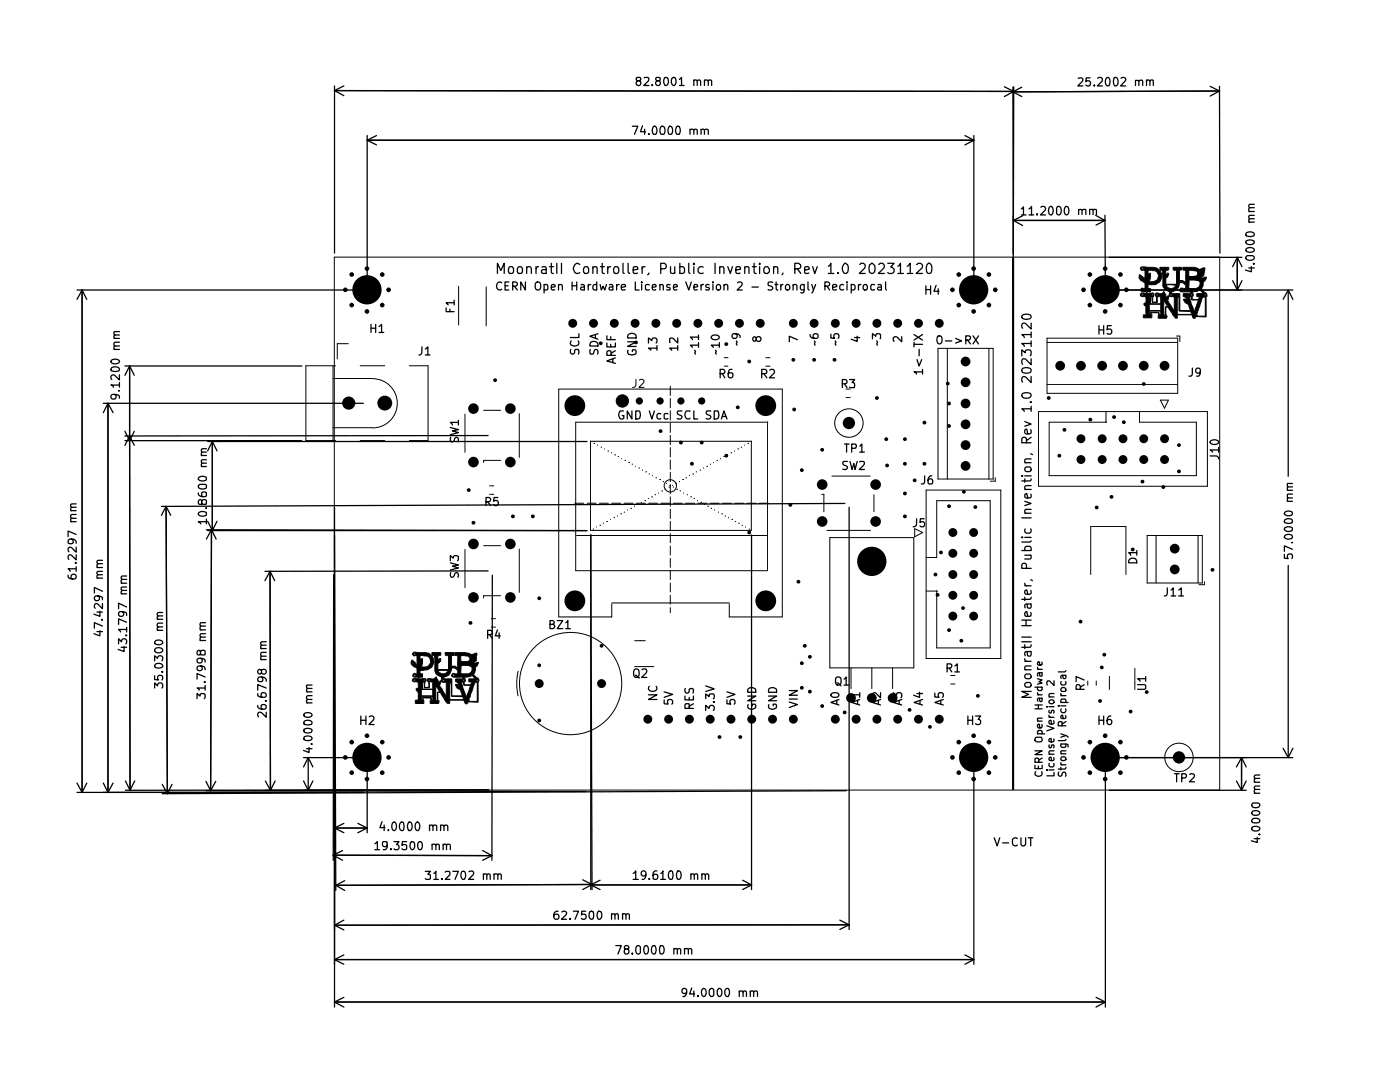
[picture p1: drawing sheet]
<svg xmlns="http://www.w3.org/2000/svg" width="279mm" height="216mm" viewBox="0 0 279 216" stroke-linecap="round" stroke-linejoin="round" font-family="sans-serif">
<g fill="none" stroke="#000" stroke-width=".2">
<path d="M66.7 51.3h176.7v106.3h-176.7zM91.5 57.1v7.8M97 57.2v7.8M227.5 55.1h.1M227.5 55.1l.6 .9 .2 .1M227.5 55.1l.2 .3M227.6 53.6h.1M227.6 53.6v-.2l.2-.1h2.4a1.75 1.75 0 0 1 1.7 1.7 1.75 1.75 0 0 1-1.5 1.8h-1.3v.8h.5v.7h-.7v.3l1.3-.1a.52 .52 0 0 1-.2 .8v1h.8v-1.1M227.6 53.6l.2 .3h2.1a1.15 1.15 0 0 1 1.3 1 1.15 1.15 0 0 1-1.1 1.3h-.7l.2-.8-.1-.9M227.6 58.8h.2M227.6 53.6h.2M227.7 57.8h.1"/>
<path d="M227.7 55.4h.1M227.7 57.8a.34 .34 0 0 0 .4 .5l.7-.1v.4l-.9-.2-.2 .2a.36 .36 0 0 0 .1 .6h.9v1.3M227.7 55.4l.7 .9v-.8M227.8 57.6h.1M227.8 57.6l-.1 .2M227.8 53.4h.3l.1 .3-.4 .1zM227.8 58.7l.2-.1 .2 .3-.4 .1zM228 57.7h.1M228 53.3h.1M228 57.7l.3 .1-.1 .2h-.3l-.1-.2M228 57.7l-.2 .1M228.2 58.8h1.6"/>
<path d="M228.3 56.1h.1M228.3 56.1a1.38 1.38 0 0 0-.9-1.3 1.26 1.26 0 0 0 1 1.6l.1 1.2h-.7M228.4 55.5h.1M228.4 53.9h.1M228.4 55.5h.7M228.5 53.9l-.1 1.6M228.6 59.2h.1M229.1 55.5h.1M229.1 53.9v.8l.4-.2M229.4 55.1h.1M229.4 55.1l-.3 .4M229.4 55.1l-.2 .4"/>
<path d="M229.5 54.5h.1M229.6 59.2h.1M229.6 59.9h.1M229.6 59.2v1.4M229.6 59.2h.2M229.8 59.2h.1M229.8 59.2l.2 1.2h1v-1.1h.6v1.3h-2.2M229.8 58.7h.3v.2l-.2 .1zM230.1 59.2h.1M230.5 58.8h.2M230.7 58.7l.4 .1-.4 .2zM230.8 59.2h.1"/>
<path d="M231.5 53.8h.1M231.5 53.8v-.5h1.8v.5l-.6 .2v.8M231.5 53.8l.5 .1 .2 3.4a1.65 1.65 0 0 0 1.1 .9l.1 1 1 .1M231.9 58.6h.1M231.9 53.9h.1M232.1 56.9h.1M232.1 56.9h2.6M232.1 55.3h.6M232.2 58.3h.1M232.2 58.3l-.3 .3M232.2 58.3v-.1l.5 .6v.6M232.2 58.5h.1"/>
<path d="M232.2 59.9h.1M232.2 58.6h-.9l-.4-.2-.4 .2v.3l.3 .3M232.2 59.9l.8 1.2M232.2 58.5v.2M232.2 59.9v3M232.7 54.8h.1M232.7 59.4h.1M232.7 56.9h.1M232.7 55.3h.1M232.7 56.9a1.03 1.03 0 0 0 1 .7 1.03 1.03 0 0 0 1-.7M232.7 59.4l.1 .1M232.8 59.5h.1"/>
<path d="M232.8 55.2h.1M232.8 55.1h.1M232.8 55.1v.1M232.8 55.2l-.1 .1M232.9 59.6l-1.3 .1M232.9 55l-.8 .1M233.1 59.7h.1M233.1 54.7h.1M233.1 59.2h.1M233.1 54.7l-.2 .3M233.1 59.2l-.2 .4M233.3 59h.1"/>
<path d="M233.3 59l-.5 .3v.2M233.3 59l-.3 .9 1.4 2.2v-2.8M233.3 58.8h.2M233.4 58.3h.4M233.7 58.7l.2 .1v.2h-.3l-.1-.2zM233.8 58.3h.1M234.2 53.8h.1M234.4 59.3h.1M234.7 56.9h.1M234.8 58.6h.1M234.8 56.2h.6M235 59.3h.1"/>
<path d="M235 59.3l-.1 3.4M235 59.3l.3-.1v2.9h2.3l.2 .6h-3.8M235.4 57.8h.1M235.4 56.2h.1M235.4 57.8l.3 .5h1.9M235.4 56.1h.7l.5 .5h-.1a1.13 1.13 0 0 0-1.1-.4zM235.7 56.3h.1M235.7 56.1h.1M235.7 57.7h.3v.3h-.4l-.1-.2zM236.1 58.8h1.5M236.2 59.7h.1M236.2 59.8h.3"/>
<path d="M236.2 59.7l.6 .1M236.3 56.3h.1M236.4 59.2h.1M236.4 59.2l.9 .1M236.5 59.8h.1M236.5 59.8l.5 .7M236.5 59.8l.2 .4M236.6 53.9h.1M236.6 59.3l.2 .5M236.6 57.6h.1M236.6 55.2h.1M236.6 57.6a1.06 1.06 0 0 0-1.2-1.2 1.71 1.71 0 0 1-1.6 1.9v.1l.3 .2h1.4v3.4h2.1l-.1-.3a1.63 1.63 0 0 0-.9-1.3l-.4-.7"/>
<path d="M236.6 53.9v2.5l-.6-.4h-.6v-2.1l.4-.1v-.5h-1.7v.5l.2 .1h.5v2.8h-2.1v-1.2a.68 .68 0 0 0 .4-1.1l-.4 .4M236.6 55.2h2.9M236.6 55.8h3.8M236.6 55.4h2.9M236.8 59.8h.1M237.2 53.9l.1 1.3M237.3 59.3h.1M237.3 59.3h.4l.1 .6h1.4l-.9 2.2M237.3 59.3l1 2.8M237.3 55.8l-.1 1.8M237.6 58.3h.1M237.6 58.3l.1 .1-.3 .2h-1.3v.6h.3"/>
<path d="M237.6 58.8l.1 .2 .3-.2M237.6 58.8l.1-.1h.3v.1M237.7 59.4h.2M237.9 59.7h.1M238 58.3h.1M238 58.8h.1M238 55.2l.7-.1a.59 .59 0 0 0 .3-.7 .59 .59 0 0 0-.7-.4l-2-.1-.2-.1v-.5h2.3l1 .5 .3-.2 .8-.2-.1 1a1.43 1.43 0 0 1-.8 1.1l.9 .1M238 58.3l.8-.1 .7-.3 .7 .7h-1.4v.6l.6 .1-.2 .5h-1l-.3-.1v-.5l.3-.3zM238.2 55.8l1.8 .2M238.8 58.8h1.5M239 54.5h.1M239 56a.57 .57 0 0 1 .5 .6 1 1 0 0 1-.8 1l-3.1-.1-.2 .3"/>
<path d="M239 54.5h.7M239.4 55.4h.1M239.5 55.4h.1M239.5 55.2h.1M239.7 54.5h.1M239.8 54.4h.1M239.8 55.6h.1M239.8 55.6l.7-.3h.3l-.3 .6a1.13 1.13 0 0 0-.4 1.1l-.3 .7 .7 .7M239.8 54.4l.3-.6-.1-.1-.3 .8M239.8 54.4l-.1 .1M239.9 55.5h.1M240 56h.1"/>
<path d="M240 59.3h.1M240 59.3h.5v3.8l-1.7-.1M240 59.3l-1.2 3.7M240.1 55.9h.1M240.1 55.8h.1M240.1 55.9l-.1 .1M240.1 55.8v.1M240.2 55.8h.1M240.3 58.8h.1M240.3 58.8l.3-.1 .1 .1-.2 .2zM240.4 55.8h.1M240.4 55.7h.1"/>
<path d="M240.4 56h.1M240.4 55.7v.1M240.5 55.6h.1M240.5 55.6l-.1 .1M240.5 58.4h.1M240.5 58.4l.4 .4-.2 .4v4h-2l-.2 .3a.44 .44 0 0 1-.4-.1 .44 .44 0 0 1-.2-.4M240.8 59.1h.1M66.5 73v14.9M66.5 75.5h7.8M67 73h-6v14.9h6M69.5 68.6h-2.2v3M71.9 73h4.9"/>
<path d="M74.4 75.6a4.9 4.9 0 0 1 4.9 4.9 4.9 4.9 0 0 1-4.9 4.9M81.7 73h3.7v14.9h-3.7M126.9 75.7v1.1a.57 .57 0 0 1-.7 .5M127.6 75.9l.1-.1a.6 .6 0 0 1 .8 .1l-.1 .5-.9 .9h1M133.8 77v1.9M133.8 79.5v1.9M144.5 73.1h.8M144.5 71.4h.8M152.8 73.1h.9M152.8 71.4h.9M168.8 77.6h.9M168.8 79.3h.9"/>
<path d="M187.2 69.5h11v26.1h-11zM189.1 69.5v26.1M197.4 69.5v26.1M209 68.3h26M209 67.5h26v11h-26zM209 76.7h26M228.3 60.6h.1M228.3 60.6v.3l.4 .2M228.4 60.6h.1M228.4 60.6l.3 .4-.2-.2M228.7 62h.1M228.7 61.1h.1"/>
<path d="M228.7 60.5h.1M228.7 62h2.9v-1.3h-2.2v-1.5v2.8M228.7 62.5l.1 .3h-.6v.6h1.7l-.1-.6M228.7 62.5h.7M228.7 61.1v1.4M228.7 60.5h-.4v.1M229.4 60.5h.1M229.4 62.8h.1M229.4 62.8v-.7h2.2v.8M229.6 62.6h.1M229.6 62.6l-.2 .2M229.8 62.8h.1"/>
<path d="M231.2 62.7h.1M231.4 60.6h.1M231.6 79.8h1.6l-.8 1.6zM232.7 62.9h.1M232.8 63.2h.1M233 61.1h.1M233 61.1l-.4 .1-.1 1.7h-1.1l-.1-.6h-1.7v.3M234 62.7h.1M234 62.7l-.9-1.4h-.4v1.5l.1 .2v.5h-1.7l.1-1.1h-1.5l.1 .4M234 62.7l.6 .8h.3v-.7h2.9l.1 .2M234.8 67.1h.7v1.1M236.7 60.2h.1"/>
<path d="M236.7 60.2l.3 .3M237 60.5h.1M237.7 62.7h.1M237.9 63h.9M238.3 62.1h.1M238.8 63h.1M66.5 85.3h7.8M71.9 87.9h4.9M92.8 82.6v7.7M96.5 81.9h3.4M97.7 98.6h.9M97.7 96.9h.9"/>
<path d="M99.9 91.9h-3.4v.4M103.6 82.5v8.8M117.9 88.1h.1M117.9 88.1v17.7h32v-17.7M117.9 88.1h32M118.5 88.5h.1M119.2 88.8h.1M120 89.2h.1M120.6 89.6h.1M121.3 90h.1M122 90.3h.1M122.7 90.8h.1"/>
<path d="M123.4 91.1h.1M124 91.5h.1M124.7 91.9h.1M125.5 92.3h.1M126.2 92.6h.1M126.8 93h.1M127.5 93.4h.1M128.2 93.8h.1M128.7 99.9h.1M128.9 94.1h.1M129.4 99.5h.1M129.5 94.6h.1"/>
<path d="M130 99.1h.1M130.2 94.9h.1M130.7 98.7h.1M130.9 95.3h.1M131.4 98.4h.1M131.7 95.7h.1M132.1 98h.1M132.3 96.1h.1M132.8 97.6h.1M133 96.4h.1M133.5 97.2h.1M133.7 96.9h.1"/>
<path d="M133.8 82v1.8M133.8 84.4v1.9M133.8 86.9v1.8M133.8 89.3v1.9M133.8 91.8v1.8M133.8 94.2v1.9M133.8 96.7v1.9M133.8 99.1v1.9M134.2 96.9h.1M134.4 97.2h.1M134.9 96.4h.1M135 97.6h.1"/>
<path d="M135.6 96.1h.1M135.7 98h.1M136.2 95.7h.1M136.4 98.4h.1M136.9 95.3h.1M137.2 98.7h.1M137.6 94.9h.1M137.8 99.1h.1M138.3 94.6h.1M138.5 99.5h.1M138.9 94.1h.1M139.2 99.9h.1"/>
<path d="M139.7 93.8h.1M140.4 93.4h.1M141.1 93h.1M141.7 92.6h.1M142.4 92.3h.1M143.1 91.9h.1M143.8 91.5h.1M144.4 91.1h.1M145.1 90.8h.1M145.9 90.3h.1M146.6 90h.1M147.2 89.6h.1"/>
<path d="M147.9 89.2h.1M148.6 88.8h.1M149.3 88.5h.1M149.9 88.1h.1M153.2 84.2v29.6M153.2 84.2h-38.3v29.7h38.3M164 98.6h.4v3.5M166 95h7.7M174.4 98.7v3.4M184.8 97.8h14.9v33.6h-14.9zM198.6 95.3v.7h-1M207.3 82.1h33.7v14.9h-33.7z"/>
<path d="M220.7 84.2h.1M220.7 82.1v2.1M227.4 82.1v2.1h11.4v10.7h-29.4v-10.7h11.3M92.8 109.6v7.7M96.5 108.9h3.4M99.9 118.9h-3.4v.4M103.6 109.6v8.6M114.7 100.4h1.8M115.1 106.8h38.1M117.2 100.4h1.8M118.4 105.6h.1M119 105.2h.1"/>
<path d="M119.6 100.4h1.8M119.7 104.8h.1M120.4 104.4h.1M121.1 104.1h.1M121.8 103.6h.1M122.1 100.4h1.8M122.5 103.3h.1M123.2 103h.1M123.9 102.5h.1M124.5 102.2h.1M124.5 100.4h1.8M125.2 101.8h.1"/>
<path d="M125.9 101.4h.1M126.6 101h.1M127 100.4h1.8M127.3 100.7h.1M128 100.2h.1M129.5 100.4h1.7M131.9 100.4h1.8M133.8 101.6v1.9M133.8 104.1v1.8M133.8 106.5v1.8M133.8 109v1.7M133.8 111.4v1.8"/>
<path d="M133.8 113.9v1.8M133.8 116.3v1.8M133.8 118.8v1.8M134.4 100.4h1.7M136.8 100.4h1.8M139.3 100.4h1.8M139.9 100.2h.1M140.5 100.7h.1M141.2 101h.1M141.7 100.4h1.8M141.9 101.4h.1M142.6 101.8h.1"/>
<path d="M143.3 102.2h.1M144 102.5h.1M144.2 100.4h1.8M144.7 103h.1M145.4 103.3h.1M146 103.6h.1M146.6 100.4h1.8M146.7 104.1h.1M147.4 104.4h.1M148.1 104.8h.1M148.8 105.2h.1M149.1 100.4h1.8"/>
<path d="M149.5 105.6h.1M151.6 100.4h1.7M165 105.8h8.7M165.6 107.3h16.8v26h-16.8zM182.5 105.5l1.6 .8-1.6 .8zM184.8 111.3h2.1v-11.4h10.7v29.4h-10.7v-11.4M184.8 117.9h2.1M186.9 117.9h.1M217.7 114.6v-9.5h7v9.5M228.9 106.8h11v9.5h-11zM230.7 106.8v9.5M239.1 106.8v9.5"/>
<path d="M240.4 116.1v.6h-1.1M82.3 135.7h.1M82.3 130.5l.3 .4 1.9-.1a1.27 1.27 0 0 1 1.4 .8 1.17 1.17 0 0 1-.9 1.5h-.8l.1-1.7-.5 .2v-.8M82.3 130.5l.2-.4 2.4 .1a1.74 1.74 0 0 1 1.7 1.9 1.74 1.74 0 0 1-1.9 1.6l-.9 .1v.7h.5v.6h-.7v.4l1.3-.1 .2 .3-.3 .4v1.1h.8v-.8l-.3-.6 .1-.4 1.6 .1M82.3 135.7v.2l.3 .2h.8M82.3 135.7h.2M82.3 130.5h.2M82.4 134.8h.1M82.5 130.5l.3-.2 .1 .3h-.4zM82.5 135.6h.4l-.1 .3-.3-.1zM82.6 132.7l-.4-.7 .2 .4 .7 .6M82.6 134.6l.2-.1 .2 .3-.4 .2z"/>
<path d="M82.7 130.1h.1M82.9 135.7h1.6M83.1 133.1a1.25 1.25 0 0 0-.9-1.4 .91 .91 0 0 0 .6 1.4l.4 .2v1.2h-.1a.41 .41 0 0 0-.7 0 .41 .41 0 0 0 .2 .6h.9v.4l-1-.1-.2 .3M83.1 137.5h.1M83.1 130.8h.1M83.1 137.5l.3 .3M83.1 137.5l.2 .2M83.1 130.8l.1 1.6M83.2 132.4h.1M83.2 132.4l-.1 .8-.4-.4M83.2 132.4h.7M83.3 137.7h.1"/>
<path d="M83.3 137.7l.1 .1M83.4 138h.1M83.4 137.8h.1M83.4 137.4h.1M83.4 136.1h.1M83.4 138l.1 1.7h-.6v.7h1.7v-.7h-.2v-.4h1.5v1.1h1.6v-.6M83.4 136.1v1.3M83.4 137.4l-.3-.1v.5l.3 .2M83.5 139.4h.6M83.9 132.4h.1M84.2 139.7h.1M84.2 132h.1"/>
<path d="M84.2 139.7l.1-.1v-.4h1.8l.1 .6M84.2 136.1v1.5h2.2l-.3-.1M84.2 136.1l-.1 2.8M84.2 139.7l-.1-.8h2.3l-.1 .9M84.2 137.5h1.9M84.2 132l-.3 .4M84.3 139.4h.1M84.3 137.5v-1.4h.3l.1 1.1h1v-1.1h.7v2.8h-2.9M84.5 139.7h.1M84.5 135.6h.3v.2l-.2 .1zM84.8 136.1h.1M85.3 135.7h.1"/>
<path d="M85.4 135.7l.1 .2M85.4 135.7l.2-.1 .3 .1-.4 .2M85.5 135.9h.1M86.1 137.5h.1M86.2 139.8h.1M86.4 136.6h1.2M86.7 135.5h.1M86.7 130.9h.1M86.8 135.4h.1M86.8 133.8h.1M86.8 133.8h2.6M86.8 135.4l-.1 .1"/>
<path d="M86.8 132.2h.7M86.8 132h.8M87 135.6h.1M87 135.4h.1M87 135.1h.1M87 135.1l.5 .7v.5M87 135.4v.2M87 135.1l-.2 .3M87 136.9h.1M87 136.9v2.9M87 136.9l.7 1.1M87.4 131.7h.1"/>
<path d="M87.4 131.7v-.8l.6-.2v-.5h-1.8v.5l.5 .1 .2 3.2a1.27 1.27 0 0 0 1.2 1M87.5 136.3h.1M87.5 133.8h.1M87.5 139.8h.1M87.5 133.8a1.03 1.03 0 0 0 .9 .7 1.03 1.03 0 0 0 1-.7M87.5 136.3v.1M87.5 136.4h.1M87.5 132.2h.1M87.5 132.1h.1M87.5 132.1v.1M87.6 136.6h.1M87.7 138h.1"/>
<path d="M87.7 138l-.4 .1v1.7h-1.1M87.8 131.6h.1M87.8 131.4h.1M87.8 136.1l-.2 .5zM87.8 131.6l-.2 .4M87.9 135.9h.1M87.9 135.9l-.4 .5M88 135.9h.1M88 135.9l-.3 .9 1.4 2.1v-2.8M88.1 135.8h.1M88.1 135h.1M88.1 135v.2"/>
<path d="M88.1 135.2h.1M88.1 135.2v.7l.1 .2M88.1 135.2h.4M88.2 136.1h.1M88.2 136.1h.9M88.3 135.6h.3v.3l-.2 .1-.2-.2zM88.5 135.2h.1M88.7 139.6h.1M88.7 139.6l-.8-1.4h-.5l.1 1.6M88.7 139.6h3.8M89.1 136.1h.1M89.4 133.8h.1"/>
<path d="M89.5 135.5h.1M89.5 133.1h.7a1.19 1.19 0 0 1 1.2 .5v-.1M89.7 136.2h.1M89.8 136.1h.1M89.8 136.1l-.1 3.5M89.8 136.1h.2M90 136.1h.1M90 136.1l.1 2.8 2.3 .1 .1 .6M90.1 134.8h.1M90.1 133.1h.1M90.1 134.8l.3 .3h2l-.1 .4M90.1 134.8h.2"/>
<path d="M90.1 133.1l.1-.1a1.16 1.16 0 0 1 1.2 .5M90.3 134.5h.1M90.3 134.5l-.2 .3M90.4 133.2h.1M90.4 133h.1M90.4 134.5h.2l.2 .3-.2 .2-.3-.1zM90.9 136.7h.1M90.9 136.6h.1M90.9 135.7h1.4M90.9 136.7h.4M90.9 136.6v.1M91.2 136.7h.1"/>
<path d="M91.2 136.7l.5 .6M91.3 136.7h.1M91.3 136.1h.1M91.3 130.8h.1M91.3 136.1h1.2M91.3 136.7l.5 .7M91.3 130.8l.1 .1M91.4 134.5h.1M91.4 133.5h.1M91.4 132.1h.1M91.4 130.9h.1M91.4 130.9v2.4l-.6-.4h-.7v-2.1h.5v-.6h-1.8l.1 .6 .6 .1v2.7h-2.1v-1.2l.2-.2a.58 .58 0 0 0 .3-.8l-.5 .3"/>
<path d="M91.4 134.5v-.6l-.7-.6h-.5l-.1 .4a1.57 1.57 0 0 1-1.6 1.4v.3l.3 .1h1.4v3.4h2.1l-.2-.6a1.19 1.19 0 0 0-.9-1.1l-.3-.5M91.4 132.7h3.7M91.4 132.1h2.9M91.4 132.2h2.8M91.7 137.3h.1M91.9 130.8l.1 1.3M92 136.1l1 3M92 132.7l-.1 1.8M92.3 135.5h.1M92.3 135.5h-1.4v.6a.67 .67 0 0 1 .6 .6l-.6-.1M92.3 135.7l.1 .2 .3-.2M92.3 135.7l.2-.1 .2 .1"/>
<path d="M92.4 139.6h.1M92.5 136.1h.1M92.5 136.3v.4h1.4l-.9 2.4M92.5 136.3h.1M92.5 136.1v.2M92.5 139.6h.1M92.6 136.6h.1M92.6 139.9h1M92.7 135.2h.1M92.7 135.7h.1M92.7 135.2l.2 .8-.3 .1v.5M92.7 135.2l1.5-.4 .7 .7h-1.3v.6h.5l-.2 .6-1.3-.1"/>
<path d="M92.9 132.7l.7 .1h1.2M93 139.1h.1M93.6 139.9h.1M93.6 135.7h1.4M93.7 132.8l.3 .1a.86 .86 0 0 1 .1 1.2l-.5 .4-3.3-.1v.1M93.8 131.4h.1M93.8 131.4a.74 .74 0 0 0-.8-.5l-2.2-.1v-.6l2.6 .1 .8 .4 .1-.1 .9-.3-.2 1.5M93.8 131.4a.72 .72 0 0 1-.8 .7M94.2 132.3h.1M94.2 132.2h.1M94.2 132.2v.1M94.2 132.1h.1"/>
<path d="M94.3 132.1h.1M94.4 131.4h.1M94.4 132.4h.1M94.4 132.4l.8 .1M94.5 131.3h.1M94.5 132.5h.1M94.5 131.3l-.1 .1M94.8 132.8h.1M94.8 130.6h.1M94.8 136.1h.1M94.8 136.1h.4v3.9h-1.6v-.4zM94.8 132.8h-.1"/>
<path d="M94.8 130.6l-.3 .5v.3h-.7M94.8 130.6l-.3 .7M94.9 132.7h.1M95 132.7h.1M95 131.8h.1M95 131.8l-.6 .6M95.1 132.7h.1M95.1 132.6h.1M95.1 132.9h.1M95.1 132.6v.1M95.2 135.6h.1M95.2 132.6h.1"/>
<path d="M95.2 135.6h.2v.3l-.4-.2M95.2 135.6l-.2 .1M95.2 132.6l-.1 .1M95.2 132.5h.1M95.2 135.3h.1M95.2 135.3l.4 .3-.2 .5v4l-1.9-.1-.2 .4-.3 .1-.5-.8h-2.8v.7h-.4l-.6-.8M95.2 132.5v.1M95.5 132.2h.1M95.5 132.2h-.5l-.3 .3M95.5 132.2l-.3 .6-.3 .3-.2 1.1-.2 .4 .7 .7M98 125.1h.9M98 123.4h.9"/>
<path d="M103.4 133.9l-.3 2.9 .3 2.1M122.1 120.3h23.4M122.1 120.5v2.6h-10.6v-45.5h44.6v45.5h-10.6v-2.6M126.7 133h3.8M126.7 127.8h2.1M133.8 121.2v1.1M169.8 133.3v4.1M174 133.3v4.1M178.1 133.3v4.1M189.7 134.8h.9M189.7 136.5h.9M217.1 135.9v.8"/>
<path d="M218.8 135.9v.8M221.4 135v2.6M226.5 133.3v4.3M87.5 140h.1"/>
<circle cx="124.2" cy="80" r="1.23"/>
<circle cx="133.8" cy="96.9" r="1.23"/>
<circle cx="169.4" cy="84.4" r="2.84"/>
<circle cx="113.9" cy="136.4" r="10.2"/>
<circle cx="235.3" cy="151.1" r="2.84"/>
</g>
<g fill="none" stroke="#000" stroke-width=".25">
<path d="M66.8 17.1v33.4M66.8 18.1l135.5 .1M66.8 18.1l1.8 1M68.6 17.1l-1.8 1M127.3 16.1l-.3-.3v-.3h.7l.2 .2-.1 .3-.8 .4v.5l.3 .2h.3l.3-.4v-.3l-.3-.3M128.6 15.5h.7l.2 .4-.1 .2-.9 1h1M130.2 16.9v.2M131.2 16.1l-.3-.3v-.3h.8v.5l-.5 .1-.3 .4 .1 .5 .5 .1a.54 .54 0 0 0 0-1M132.6 15.5h.4a.87 .87 0 0 1 .4 .8 .87 .87 0 0 1-.6 .8l-.2-.1-.1-.5zM134.2 15.5h.2a.83 .83 0 0 1 .6 .6 .83 .83 0 0 1-.3 .8l-.1 .2a.91 .91 0 0 1-.4-1.6zM135.6 15.9l.4-.4v1.6M135.6 17.1h.9"/>
<path d="M138.5 16.1l.1-.1h.5v1.1M138.5 16v1.1M139.1 16.2a.35 .35 0 0 1 .4-.3 .35 .35 0 0 1 .3 .3v.9M140.6 16.1l.2-.1h.5l.1 1.1M140.6 16v1.1M141.4 16.2l.1-.2h.4l.1 1.1M200.4 17.3l1.9 .9M202.1 18.3l1.8 1M202.3 17.3l-.1 33.4-.1-33.3M202.3 18.2l-1.9 1.1M203.9 17.4l-1.8 .9M215.2 15.6h.8l.1 .4-.1 .2-.9 .9h1"/>
<path d="M217.6 15.5h-.8l-.1 .8 .3-.2h.4a.6 .6 0 0 1 0 1h-.4l-.3-.1M218.4 17v.1M219.1 15.6l.6-.1 .2 .1 .1 .4-.1 .2-.9 .9h1M220.8 15.6l.2-.1a1.03 1.03 0 0 1 .2 1.6 .91 .91 0 0 1-.4-1.5zM222.3 15.6l.2-.1a.89 .89 0 0 1 .7 .8 .89 .89 0 0 1-.7 .8h-.1l-.2-.6zM223.7 15.6l.6-.1 .3 .1 .1 .4-1.1 1.1h1.1M226.6 16.1l.6-.1 .1 1.1M226.6 16v1.1M227.3 16.2l.1-.2h.6v1.1M228.8 16.1l.1-.1a.36 .36 0 0 1 .6 .2v.9M228.8 16v1.1M229.5 16.2l.2-.2h.5v1.1"/>
<path d="M241.5 17.2l1.9 1M243.4 17.2l.1 33.3M243.4 18.2l-41.3 .1M243.4 18.2l-1.9 1M73.3 27.1v30M73.3 28h121.1M73.3 28l1.8 .9M75.1 27.1l-1.8 .9M126.2 25.2h1.1l-.7 1.6M128.2 25.1l-.4 1.2h1M128.7 25.8v1M129.5 26.7v.1"/>
<path d="M130.3 25.4l.3-.2a1.03 1.03 0 0 1 .3 1.6h-.5l-.1-.3-.1-.6zM132 25.3l.1-.1a.92 .92 0 0 1 .7 .7 .92 .92 0 0 1-.3 .9h-.5l-.2-.3-.1-.6zM133.6 25.2a.92 .92 0 0 1 .7 .7 .92 .92 0 0 1-.3 .9h-.4l-.3-.6 .1-.7zM135 25.4l.4-.2a1.35 1.35 0 0 1 .2 1.6h-.5l-.2-.3-.1-.6zM137.7 25.9l.5-.1 .3 .2v.8M137.7 25.8v1M138.5 26l.1-.2 .5 .2v.8M139.9 25.9l.5-.1 .2 .2v.8M139.9 25.8v1M140.6 26l.2-.2 .6 .2v.8M192.6 27.1l1.8 .9M194.4 27.1v30"/>
<path d="M194.4 28l-1.8 .9M15.4 57.9h57.1M16.4 57.9v100.2M16.4 57.9l.9 1.8M16.4 57.9l-1 1.8M90.6 59.9v.9M99.3 54.6v-2.1l.6 1.5 .7-1.5v2.1M100.1 56.4a.76 .76 0 0 0-1 .4 .76 .76 0 0 0 .3 1l.4 .1 .3-.2M100.8 57h.6M101.6 56.3h-.8v1.6h.8M101.6 53.3l.6-.1 .3 .4v.6l-.3 .4h-.4l-.3-.4v-.6zM102.3 57.1l.8-.1 .2-.2-.1-.4-.3-.1h-.6v1.6"/>
<path d="M102.7 57.1l.6 .8M103.4 53.3l.5-.1 .4 .4v.6l-.4 .4-.5-.1-.1-.3v-.6zM104.9 56.3v1.6l-1-1.6v1.6M105.1 53.5a.52 .52 0 0 1 .8-.2l.1 .3v1M105.1 53.2v1.4M106.9 56.5a.55 .55 0 0 1 .6-.2 .55 .55 0 0 1 .4 .5v.6a.55 .55 0 0 1-.5 .5 .55 .55 0 0 1-.6-.5zM107 53.2v1.4M107.5 53.2l-.4 .1-.1 .3M108.2 53.3h.7l.1 1.3M108.6 56.9l.5-.1 .2 .3v.7h-.7M108.6 56.8v1.7M109 53.7l-.8 .2-.1 .2 .1 .4h.8"/>
<path d="M109.7 53.2h.7M110 57.4l.8-.2-.1-.3-.4-.1-.3 .2 .1 .8h.6M110 52.5v1.8l.1 .2 .3 .1M111.1 52.5v2.1M111.5 56.9l.2-.1 .4 .1 .1 1M111.5 56.8v1.1M112.1 52.5v2.1M114.2 57h.9M114.2 56.3v1.6M115.1 56.3v1.6M115.7 52.8l-.4-.3a1.03 1.03 0 0 0-.9 1.1 1.03 1.03 0 0 0 .9 1l.4-.2M116 56.9h.5l.1 1"/>
<path d="M116.6 57.2l-.5 .1-.2 .2 .2 .4 .5-.1M116.6 53.3l.5-.1 .4 .4v.6l-.4 .4-.5-.1-.1-.3v-.6zM117.4 56.8v1.1M117.9 56.8l-.3 .1-.2 .2M118.3 53.5a.45 .45 0 0 1 .5-.3 .45 .45 0 0 1 .4 .4v1M118.3 53.2v1.4M119.1 56.9l-.4-.1-.4 .3v.5l.2 .2h.6M119.1 56.3v1.6M119.8 56.8l.2 1.1 .4-.8 .3 .8 .3-1.1M119.8 53.2h.8M120.2 52.5v1.8l.1 .2 .3 .1M121.3 53.2v1.4"/>
<path d="M121.6 56.9h.6l.1 1M121.9 53.2l-.4 .1-.2 .3M122.3 57.2l-.5 .1-.3 .2 .3 .4 .5-.1M122.6 53.3l.5-.1 .4 .4v.6l-.4 .4-.5-.1-.1-.3v-.6zM123.1 56.8v1.1M123.6 56.8l-.4 .1-.1 .2M124 57.4l.8-.2v-.3l-.6-.1-.2 .2 .1 .8h.7M124.3 52.5v1.8l.3 .3M125.3 52.5v1.8l.4 .3M126.4 53.9l.9-.2-.1-.4-.6-.1-.2 .4v.9h.8M126.8 56.3v1.6h.8M128.1 56.3v.1"/>
<path d="M128.1 56.8v1.1M128.1 53.2v1.4M128.7 53.2l-.4 .1-.2 .3M129.5 54.5l-.3 .3M129.6 56.9l-.5-.1-.3 .1v.8l.3 .2 .5-.1M130.2 57.4l.7-.2-.1-.4-.5 .1-.1 .7 .2 .3 .5-.1M131.7 56.9l.2-.1 .4 .1 .1 1M131.7 56.8v1.1M131.9 53.6h.7a.53 .53 0 0 0 .3-.8l-.3-.3h-.7v2.1M133.7 56.9l-.4-.1-.2 .2v.3l.6 .1v.4h-.6M133.8 53.2v1.1a.52 .52 0 0 0 .9 .1M134.4 57.4l.8-.2-.1-.3-.4-.1-.3 .2 .1 .8h.6"/>
<path d="M134.7 53.2v1.4M135.7 53.3h.7l.2 .3v.6l-.2 .3h-.7M135.7 52.5v2.1M136.9 56.3l.6 1.6 .5-1.6M137.5 52.5v1.8l.2 .3M138.5 57.4l.7-.2-.1-.3-.5-.1-.1 .2 .1 .8h.5M138.5 52.5v.3M138.5 53.2v1.4M139.9 56.8v1.1M140.3 53.3l-.2-.1a.63 .63 0 0 0-.8 .4v.6a.72 .72 0 0 0 1 .3M140.4 56.8l-.3 .1-.2 .2M141.5 56.9l-.4-.1-.3 .2 .1 .3 .6 .1v.4h-.7"/>
<path d="M142.3 56.3v.1M142.3 56.8v1.1M142.7 52.5v2.1M143.1 56.9l.5-.1 .2 .3v.5l-.2 .3h-.3l-.3-.3v-.5zM143.6 53.5l.3-.3 .5 .1 .1 1.3M143.6 53.2v1.4M144.5 56.9l.2-.1 .5 .1v1M144.5 56.8v1.1M145.2 53.2l.6 1.4 .4-1.4M146.9 53.9l.9-.2-.1-.4-.6-.1-.2 .4v.9h.8M147.2 56.4l.6-.1 .3 .4-.1 .2-.9 1h1M148.6 53.5a.45 .45 0 0 1 .5-.3 .45 .45 0 0 1 .4 .4v1"/>
<path d="M148.6 53.2v1.4M150.1 57.3h1.2M150.2 53.2h.7M150.5 52.5v1.8l.1 .2 .3 .1M151.6 52.5v.3M151.6 53.2v1.4M152.6 53.3a.61 .61 0 0 1 .9 .3v.6a.63 .63 0 0 1-1 .2l-.1-.8zM154.2 56.3h-.7l-.2 .1v.5l.8 .3 .1 .2v.2l-.3 .3-.6-.1M154.4 53.5a.44 .44 0 0 1 .4-.3 .44 .44 0 0 1 .4 .4v1M154.4 53.2v1.4M154.6 56.8h.6M154.9 56.3v1.3l.3 .3"/>
<path d="M155.8 56.8v1.1M156.3 56.8l-.5 .3M156.3 54.5l-.2 .3M156.8 56.9l.3-.1 .3 .1 .2 .2v.5a.47 .47 0 0 1-.4 .3 .47 .47 0 0 1-.4-.3zM158.3 56.9l.2-.1 .5 .1v1M158.3 56.8v1.1M158.6 53.6h.8l.3-.1a.61 .61 0 0 0-.3-1h-.8v2.1M159.1 53.6l.7 1M160.5 56.8v1.3l-.4 .4-.3-.1M160.5 56.9l-.4-.1-.3 .1-.1 .7a.52 .52 0 0 0 .8 .2M160.6 53.9l.9-.2-.1-.4-.6-.1-.2 .4 .1 .9h.7M161.2 56.3v1.3l.3 .3"/>
<path d="M162 56.8l.3 1.1M162.2 53.2l.4 1.4 .5-1.4M162.8 56.8l-.8 1.7M164.6 57.1l.8-.1 .2-.2-.1-.4-.3-.1h-.6v1.6M165.1 57.1l.5 .8M165.3 53.1l.5-.6v2.1M165.3 54.6h1.1M166.2 57.4l.8-.2-.1-.3-.5-.1-.2 .2v.8h.7M167.3 54.4v.2M168.4 56.9l-.5-.1-.2 .1-.1 .7a.52 .52 0 0 0 .8 .2M168.4 52.8l.2-.3 .4 .2a1.37 1.37 0 0 1 .1 1.7l-.3 .2-.4-.2a1.33 1.33 0 0 1 0-1.6zM169 56.3v.1"/>
<path d="M169 56.8v1.1M169.9 56.9l.4-.1 .3 .3v.5l-.1 .2h-.6M169.9 56.8v1.7M171.3 56.8v1.1M171.6 52.8l.2-.3h.5a.65 .65 0 0 1 .3 1l-1.1 1.1h1.2M171.8 56.8l-.3 .1-.2 .2M172.3 56.9l.3-.1 .4 .1 .1 .7-.3 .3h-.2l-.3-.3zM173.6 52.8l.3-.3a1.08 1.08 0 0 1 .8 1.1 1.08 1.08 0 0 1-.8 1 .95 .95 0 0 1-.5-1.3zM174.5 56.9l-.5-.1-.2 .3 .1 .7h.6M175.2 56.9h.6l.1 1M175.4 52.8l.2-.3h.5a.65 .65 0 0 1 .3 1l-1.1 1.1h1.2M175.9 57.2l-.5 .1-.3 .2 .3 .4 .5-.1"/>
<path d="M176.7 56.3v1.3l.2 .3M177.2 52.5h1.2l-.6 .8h.2l.4 .4v.5l-.4 .4h-.6l-.2-.2M179.2 53.1l.5-.6v2.1M179.2 54.6h1.1M181.1 53.1l.6-.6v2.1M181.1 54.6h1.1M182.9 52.8l.4-.3h.4l.3 .3 .1 .3-.1 .4-1.2 1.1h1.3M184.8 57v1.7M184.8 57.8h.9M185.3 52.5a1.1 1.1 0 0 1 .6 1.7l-.2 .3-.4 .1a1.38 1.38 0 0 1 0-2.1zM185.7 57v1.7M186.8 56.9l-.4 1.2h1"/>
<path d="M187.2 57.6v1.1M202.2 43.1v14M202.2 44h18.3M202.2 44l1.9 1M203.8 41.7l.5-.4v1.6M203.8 42.9h1M204.1 43.1l-1.9 .9M205.4 41.7l.5-.5v1.7M205.4 42.9h.9M207 42.7v.2M207.7 41.4l.2-.2h.4l.3 .2 .1 .3-.1 .3-1 .9h1.1M209.5 41.3l.2-.1a.95 .95 0 0 1 .5 .8 .95 .95 0 0 1-.5 .9 1.1 1.1 0 0 1-.2-1.6z"/>
<path d="M210.9 41.4l.3-.2a.89 .89 0 0 1 .6 .8 .89 .89 0 0 1-.6 .9l-.3-.4zM212.7 41.2a.92 .92 0 0 1 .6 .8 .92 .92 0 0 1-.5 .9 1.1 1.1 0 0 1-.1-1.7zM215.3 41.9l.4-.1 .2 .2v.8M215.3 41.8v1M215.9 42l.3-.2h.4l.1 1M217.5 41.9l.6-.1v1M217.5 41.8v1M218.1 42l.1-.2h.5l.1 1M218.7 43l1.8 1M220.5 43l.1 14.1M220.5 44l-1.8 .9M221.4 57.9h36.6"/>
<path d="M221.4 51.4h26.5M246 56l.9 1.9M246.9 51.4v6.5M246.9 51.4l1 1.8M246.9 51.4l-.9 1.8M247.9 56l-1 1.9M248.7 51.2l.3-.2h1l.3 .4a.89 .89 0 0 1-.8 .6 .89 .89 0 0 1-.9-.6zM248.7 49.7a1.1 1.1 0 0 1 1.6 .1 .95 .95 0 0 1-.8 .5 .95 .95 0 0 1-.9-.5zM248.7 48a1.35 1.35 0 0 1 1.6 .2 .89 .89 0 0 1-.8 .6 .89 .89 0 0 1-.9-.6zM248.7 46.5a1.1 1.1 0 0 1 1.6 .2l-.2 .4-.8 .1-.6-.2zM249.2 53.5h1.1M249.2 44.3h1.1"/>
<path d="M249.2 42.2h1.1M249.7 53.2v1l-1.2-.3M250.1 52.6h.2M250.3 43.6h-.9l-.2 .3 .2 .4M250.3 43h-.9l-.2 .1 .2 .5M250.3 41.4h-.9l-.2 .3 .2 .5M250.3 40.8h-.9l-.2 .2 .2 .4M257.1 57.9v37.1M257.1 57.9l.9 1.8M257.1 57.9l-1 1.8M22.1 72a1.03 1.03 0 0 1 1.7 .2 .95 .95 0 0 1-.9 .4 .95 .95 0 0 1-.8-.6zM22.2 73.4a1.1 1.1 0 0 1 1.6 .2l-.1 .4-.9 .1-.6-.1z"/>
<path d="M22.7 69.7h1.1M22.7 67.5h1.1M22.9 78.7l.3 .3-.1 .5-.2 .1-.6-.1-.2-.5 .4-.3h.6a.63 .63 0 0 1 .7 .8M23.7 77.9h.1M23.8 76.8h-1.7l.5 .5M23.8 74.8v1l-.9-.9a.52 .52 0 0 0-.8 .2v.4l.2 .2M23.8 69l-1 .1-.1 .4 .2 .2M23.8 68.3l-1 .1-.1 .4 .3 .2M23.8 66.8h-.8a.37 .37 0 0 0-.3 .4 .37 .37 0 0 0 .2 .3M23.8 66.2h-1l-.1 .4 .3 .2M23.8 76.3v1M24.9 73h35.3"/>
<path d="M25.9 73v14.9M25.9 73l.9 1.9M25.9 73l-1 1.9M74 64.7v1.6M74 65.5h1M75 64.7v1.6M75.6 65.2l.6-.5v1.6M75.6 66.3h1M84.2 69.2v1.1a.55 .55 0 0 1-.6 .5M84.9 69.6l.5-.4v1.6M84.9 70.8h.9M89 61.4v.8h1.6"/>
<path d="M89.8 61.7v.5M90.6 60.4h-1.6l.5 .4M113.9 69.7l-.1 .6 .4 .4 .4-.2 .3-.8h.5l.1 .3-.1 .7M114 68l-.2 .5a.96 .96 0 0 0 1.7 0l-.1-.5M115.5 66.6v.8h-1.7M117.8 69.7v1h.5l.5-1 .4 .1 .1 .3v.6M117.9 68.3a.88 .88 0 0 1 1-.1 .88 .88 0 0 1 .4 .8h-1.6zM118.8 66.8v.7M119.3 66.6l-1.6 .5 1.6 .6M121.1 68.5v.7h1.7v-.7M121.1 67v.8h1.7M121.9 67.2v.6"/>
<path d="M121.9 68.7v.5M122 70.9l-.1-.8h-.7l-.1 .8h1.7M122.3 71.6v.7M122.8 71.4l-1.7 .6 1.7 .5M122.8 70l-.8 .5M125.3 68.2h1.7l-1.7 .9h1.7M125.3 69.9a.55 .55 0 0 0 .4 .8h.8a.54 .54 0 0 0 .4-.3 .54 .54 0 0 0-.1-.6h-.6v.3M125.3 66.8a.9 .9 0 0 1 1.1-.2 .9 .9 0 0 1 .6 .8h-1.7zM129.4 68.5v-1.1l.7 .5 .2-.5 .6 .1 .2 .3v.4l-.2 .3M131.1 69.5h-1.7l.5 .4M131.1 69v.9M135.3 69.5h-1.7l.5 .4"/>
<path d="M135.3 67.4v1.1l-1-1-.2-.1-.5 .2 .1 .8M135.3 69v.9M138.6 69.9l.2 .2-.2 .3 .2 .3M139.4 68.9h-1.6l.4 .4M139.4 67.3h-1.6l.4 .5M139.4 66.8v1M139.4 68.4v.9M142 67.1a.9 .9 0 0 1 1.6 .3 .91 .91 0 0 1-1.7-.1zM142.8 69.9l.2 .2-.2 .3 .2 .3M143.6 68.9h-1.7l.5 .4M143.6 68.4v.9M143.7 74.5h.9a.52 .52 0 0 0-.2-.8h-.7v1.7"/>
<path d="M144.1 74.5l.6 .9M146.1 73.7h-.3a1.18 1.18 0 0 0-.2 1.7l.6-.2 .1-.6-.4-.2h-.3l-.3 .2M146.8 66.6l.2 .2 .1 .4-.3 .3h-.5a.54 .54 0 0 1 0-.9l1.1 .1 .3 .3v.4M146.9 68l.2 .3-.2 .3 .2 .3M150.9 67.4l.4-.2h.3l.2 .2v.4l-.2 .3h-.3l-.4-.3v-.4l-.3-.2-.4 .2v.4a.34 .34 0 0 0 .4 .3 .34 .34 0 0 0 .3-.3M152 74.5h1v-.6l-.3-.2h-.7v1.7M152.4 74.5l.6 .9M153.6 73.9l.6-.2 .3 .2 .1 .3-.1 .3-1 .9h1.1M159.1 67.8l-1.6-.7v1.1M161.7 66.8a.68 .68 0 0 0 .6 .7h.7a.54 .54 0 0 0 0-.9h-.4l-.3 .3v.5l.3 .1M162.5 68l.2 .3-.2 .3 .2 .3M165.8 66.7v.7l.8 .1-.2-.2 .1-.5 .3-.2h.4a.59 .59 0 0 1 .1 .9"/>
<path d="M166.7 68l.1 .3-.1 .3 .1 .3M168.1 76.6l.8-.1 .1-.2v-.4l-.3-.2h-.6v1.6M168.5 76.6l.5 .7M169.5 75.7h1.1l-.5 .6 .4 .1v.9h-1M170.6 67.4h1M171.1 67.1v1l-1.2-.4M174.1 67.6v-1l.7 .5v-.3l.2-.2 .6 .1v.9M175 68l.1 .3-.1 .3 .1 .3M180 67.2v1l-1-.9a.52 .52 0 0 0-.7 .1v.5l.1 .2M182.4 68.3v.9M182.4 68.7h1.7M182.4 66.8l1.7 1.1"/>
<path d="M183 71.8l.4 1.2 .5-1.2M183.4 69.7v1.3M184.1 74.2h-1.7l.5 .4M184.1 73.7v.9M184.1 66.8l-1.7 1.1M187.2 67.1l.4-.1a.87 .87 0 0 1 .4 .9 .87 .87 0 0 1-.6 .7l-.2-.1-.2-.5zM188.7 68h1.2M190.7 67.5l1.2 .5-1.2 .5M192.7 67.9l.8-.1 .2-.3-.1-.4-.9-.1v1.6M193.1 67.9l.6 .7M194.2 67l1.1 1.6M195.3 67l-1.1 1.6"/>
<path d="M203.9 71v-1.2l.7 .6 .1-.4 .2-.2h.5l.3 .2a.92 .92 0 0 1-.1 1M204 78.6a1.31 1.31 0 0 1 1.8 .2 .97 .97 0 0 1-.9 .7 .97 .97 0 0 1-1-.7zM204 73.6a1.31 1.31 0 0 1 1.8 .2l-.1 .4a1.17 1.17 0 0 1-1.8-.2zM204 62.9a1.31 1.31 0 0 1 1.8 .2v.2a1.21 1.21 0 0 1-1.9 0zM205.8 75.1v1.2l-1.1-1.1-.3-.1-.3 .1-.2 .3v.5l.2 .2M205.8 71.6v1.2l-1.1-1.1-.3-.1-.3 .1-.2 .2 .2 .8M205.8 68.5h-1.9l.4 .4 .1 .2M205.8 66.8h-1.9l.4 .3 .1 .3M205.8 64.5v1.2l-1.1-1.1-.3-.1-.3 .1-.2 .2v.4l.2 .3M205.8 66.3v1.1M205.8 68v1.1M219.3 65v1.7"/>
<path d="M219.3 65.8h1M220.3 65v1.7M221.8 65h-.8l-.1 .8 .3-.1h.4l.3 .2-.1 .6-.2 .2h-.4l-.3-.2M238 73.4l-.1 1.5-.2 .2h-.4M239.6 74.1l-.4 .4-.4-.1-.2-.3 .2-.6 .4-.1 .3 .2a1.35 1.35 0 0 1-.3 1.5h-.4M20.6 80.5h51.9M21.5 80.5v77.6M21.5 80.5l1.1 1.8M21.5 80.5l-.9 1.8M24.9 87.9h35.3M24.9 86.1l1 1.8M25.9 87l.1 70.7"/>
<path d="M25.9 87l.9 1.9M25.9 87l-1 1.9M26.8 86.1l-.9 1.8M39.6 98.3a.68 .68 0 0 0 .7 .8l.8-.1v-.7l-.6-.1-.2 .1v.6l.2 .2M39.7 96.8l.2-.2h1l.3 .2v.5a1.1 1.1 0 0 1-1.6-.1zM39.7 95.3l.6-.3 .6 .1 .3 .2v.4a1.03 1.03 0 0 1-1.6-.2zM40.2 93.1h1M40.2 90.9h1M41.2 92.4h-.9l-.1 .3 .1 .4M41.2 91.7h-.9l-.1 .2 .1 .5M41.2 90.2h-.9l-.1 .3 .1 .4M41.2 89.5h-.9l-.1 .3 .1 .4"/>
<path d="M41.4 88.1h75.7M42.4 88.1v17.8M42.4 88.1l.9 1.9M42.4 88.1l-1 1.9M89.9 85.3l1.6 .4-1.2 .3 1.2 .3-1.6 .4M90 87.2l-.1 .7 .2 .3 .5-.3 .3-.6h.4a.64 .64 0 0 1 .1 .9M91.5 84.3h-1.6l.4 .5M91.5 83.9v.9M97.4 86.9l-72.5 .1M99.4 99.3h-.8l-.1 .7 .3-.1h.5l.1 .3v.4a.59 .59 0 0 1-.9 .1M124.4 82h-.7a1.03 1.03 0 0 0 .3 1.6l.5-.2v-.5h-.3M126.1 82v1.6l-.9-1.6v1.6"/>
<path d="M126.9 82h.7a1.03 1.03 0 0 1-.3 1.6h-.4zM129.6 82l.5 1.6 .5-1.6M131.9 82.6l-.5-.1-.3 .3v.5l.2 .2h.6M133.3 82.6l-.5-.1-.3 .2v.7l.3 .2 .5-.1M136.1 82h-.8l-.1 .3 .1 .4 .8 .4-.1 .3a.64 .64 0 0 1-.8 .1M137.7 82.1l-.7-.1a.83 .83 0 0 0-.3 1 .83 .83 0 0 0 .9 .5l.1-.1M138.5 82v1.6h.7M141.9 82h-.8l-.2 .3 .2 .4 .8 .4-.1 .3a.64 .64 0 0 1-.9 .1M142.5 82h.7a1.03 1.03 0 0 1-.2 1.6h-.5zM144 83.6l.5-1.6 .6 1.6M144.1 83.1h.8M168.5 88.6h1"/>
<path d="M169 88.6v1.6M169.1 92.1l-.8 .1a.45 .45 0 0 0 .1 .6l.7 .4-.1 .3a.64 .64 0 0 1-.8 .1M169.6 92.1l.5 1.6 .3-1.2 .2 1.2 .5-1.6M170 89.5l.8-.1v-.7l-.8-.1v1.6M171.6 89l.4-.4v1.6M171.6 92.2l.7-.1 .2 .4-.1 .3-.9 .9h1M171.6 90.2h.9M184.5 95l-.1 1.4-.1 .2h-.4M186 95a.68 .68 0 0 0-.8 .6v.7l.2 .3 .7-.1v-.6l-.1-.3-.5-.1-.3 .4M203.9 95h.2M204.5 84.1l1.3 .5-1.3 .4M204.5 95.5v.7"/>
<path d="M204.5 97.7h1.3M204.5 95h1.3M204.5 92.3h1.3M204.6 93.3l.3-.1h.5l.3 .1 .1 .5-.4 .3h-.5l-.4-.3zM204.9 88.3l-.1-.9-.3-.2-.4 .1-.2 .3v.7h1.9M205.6 80.2h.2M205.7 98.6l.1 .5-.3 .3-.9-.1v-.7l.3-.1 .2 .9M205.7 90.6l.3 .1M205.7 85.7l.1 .6-.3 .3-.9-.1v-.8l.3-.1 .2 1M205.8 96.9l-1.2 .1-.1 .4 .2 .3M205.8 95.5l-.1 .4-.2 .1h-1.6M205.8 91.6l-1.2 .1-.1 .4 .2 .2"/>
<path d="M205.8 81.6h-1.9l.5 .5M205.8 87.2l-.9 .7M205.8 81.1v1M241.5 91h1.2a.55 .55 0 0 1 .5 .6M241.6 88a1.03 1.03 0 0 1 1.6 .3 .98 .98 0 0 1-1.7-.1zM243.2 89.8h-1.7l.5 .4M243.2 89.3v.9M256.9 97.8h1M257.9 99.4h-1l.1 .6M257.9 98.6l-1 .1v.6l.2 .1M257.9 97.2h-1l.1 .6M257.9 96.5h-1v.6l.2 .1"/>
<path d="M13.6 114.8l.1 .5a1.23 1.23 0 0 0 1.5 0l-.2-.6-.5-.1-.3 .3v.4l.3 .2M14.1 104.1h1.1M14.1 101.9h1.1M14.3 107.6l.3 .3-.1 .5-.2 .1-.6-.1-.1-.5 .2-.2a1.1 1.1 0 0 1 1.4 .4v.3M15 112.3h.2M15.2 113.5h-1.6l.4 .5M15.2 110.7v1l-.9-.9-.3-.1-.4 .3 .2 .6M15.2 109.2v1l-.9-.9-.3-.1-.4 .2v.5l.2 .2M15.2 106.6l-1.6-.6v1.1M15.2 103.4l-1 .1-.1 .3 .2 .3M15.2 102.7h-1l-.1 .5 .3 .2M15.2 101.2h-.8a.37 .37 0 0 0-.3 .3 .37 .37 0 0 0 .2 .4"/>
<path d="M15.2 100.5l-1 .1-.1 .4 .3 .2M15.2 113.1v.9M19.3 115.4h1.1M19.3 113.2h1.1M19.5 118.9l.4 .3v.3l-.4 .3h-.4l-.3-.3v-.3a1.1 1.1 0 0 1 1.6 .1v.4M20.4 118l-1.6-.8v1.1M20.4 114.7l-1 .1-.1 .4 .2 .2M20.4 114l-1 .1-.1 .3 .3 .3M20.4 112.5l-1 .1-.1 .4 .2 .2M20.4 111.8h-.8a.35 .35 0 0 0-.3 .3 .35 .35 0 0 0 .3 .4M24.2 118.5h1.1M24.2 116.4h1.1"/>
<path d="M25.3 117.8l-1 .1-.1 .4 .1 .2M25.3 117.1l-1 .1-.1 .4 .2 .2M25.3 115.6l-1 .1-.1 .4 .1 .3M25.3 114.9h-.9a.35 .35 0 0 0-.2 .4 .35 .35 0 0 0 .2 .3M33.1 101l.3 57.4M33.1 101l1 1.8M33.1 101l-.9 1.8M39.7 102.3l.6-.2 .6 .1 .3 .1v.4a1.03 1.03 0 0 1-1.6-.2zM40.3 100l.3-.3 .6 .2-.1 .7h-.7l-.2-.8-.3-.1-.2 .2-.1 .5 .2 .2h.4l.1-.2M41.1 101.4h.1M41.2 104.1h-1.6l.5 .4M41.2 105.7l75.9 .2h-75.7"/>
<path d="M41.2 103.6v.9M41.4 104l1 1.9M42.2 105.7l-.2 52.1M42.2 105.7l.9 1.9M42.2 105.7l-1 1.9M43.3 104l-.9 1.9M53.9 114l.1 43.7M53.9 114l.9 1.9M53.9 114l-1 1.9M66.6 114.7l-.1 57M66.8 106.9l.2 70.8M66.8 101.3v99.7"/>
<path d="M89.9 112.3l1.6 .4-1.2 .3 1.2 .3-1.6 .4M89.9 111.9v-1l.6 .5 .1-.4h.8l.1 .6-.2 .3M90 114.3a.67 .67 0 0 0 .1 .9l.5-.2 .3-.7h.4a.64 .64 0 0 1 .1 .9M97 100.1l.7-.1 .2-.2-.1-.4-.2-.1h-.6v1.6M97.3 100.1l.6 .8M97.4 113.9l-44.5 .1M98.3 114.8l-.1 56.9M150 106.7v70.8M168.6 100.5l-136.4 .5M169.5 101.2v84.3M182.9 103.5v1.1a.57 .57 0 0 1-.7 .5M184.4 103.5h-.7l-.1 .8 .3-.2 .5 .1 .1 .2-.1 .5-.2 .2-.6-.2"/>
<path d="M203.9 107.2h.2M203.9 109.9h1.9M203.9 103.3h1.9M204.5 116.4l.1 .3 .3 .2M204.5 100l1.3 .5-1.3 .4M204.5 119.2v.6M204.5 116.9h1.3M204.5 110.8h1.3M204.5 107.2h1.3M204.5 102.4h1.3M204.6 109.9l-.1-.6 .4-.3 .7 .1 .2 .2-.1 .6M204.6 105.5l-.1 .5 .4 .4 .7-.1 .2-.3-.1-.5"/>
<path d="M204.9 113.4l-.1-.8-.3-.2-.4 .1-.2 .2v.7h1.9M205.6 110.8l.2 .2-.1 .5h-1.2M205.7 117.8l.1 .5-.3 .3-.9-.1v-.7l.3-.1 .2 .9M205.7 115.7l.3 .2M205.8 119.2l-.1 .3-.2 .1h-1.6M205.8 107.9l-.3 .3h-1.6M205.8 101.6l-1.2 .1-.1 .5 .2 .2M225.3 111.7a.84 .84 0 0 1 1-.3 .84 .84 0 0 1 .6 .9h-1.6zM226.9 110.3h-1.6l.4 .5M226.9 109.9v.9M233 117.3l-.1 1.4-.1 .1-.4 .1M233.7 117.7l.4-.4v1.6"/>
<path d="M233.7 118.9h1M235.2 117.7l.6-.4v1.6M235.2 118.9h1M256.3 110.6v.8l.8 .1-.2-.3 .1-.5 .3-.2 .6 .1v.9M256.4 106.9a.99 .99 0 0 1 1.5 .2 .83 .83 0 0 1-.6 .6 .83 .83 0 0 1-.8-.3l-.2-.2zM256.4 105.3l.5-.2a.86 .86 0 0 1 1 .4v.1a.87 .87 0 0 1-.8 .5 .87 .87 0 0 1-.8-.6zM256.4 103.8a.99 .99 0 0 1 1.5 .1v.4a1.19 1.19 0 0 1-1.6-.2zM256.4 102.2a.99 .99 0 0 1 1.5 .2 .83 .83 0 0 1-.6 .6 .83 .83 0 0 1-.8-.3l-.2-.2zM256.9 100h1M257.1 112.8v38.4M257.9 108.2h.1M257.9 109.6l-1.6-.7v1.1"/>
<path d="M19.3 126h1.1M19.3 122.1h1.1M19.9 125.9v1l-1.1-.5M19.9 122v1l-1.1-.4M20.3 123.7h.1M20.4 124.9l-1.6-.7v1.1M20.4 120.4v1.1l-.9-1-.4-.1a.59 .59 0 0 0-.1 1M23.7 128.5v-1l.6 .6 .1-.5h.7l.2 .2v.4l-.2 .3M24.2 129.2h1.1M24.3 122l.4 .3v.3l-.4 .4h-.4l-.2-.2v-.5a1.1 1.1 0 0 1 1.6 .2v.3M24.8 129v1l-1.2-.4M25.1 126.8h.2"/>
<path d="M25.3 125.6h-1.6l.4 .5M25.3 124.2l-1.6-.7v1.1M25.3 121.1l-1.6-.7v1.1M25.3 125.2v.9M30.9 137.3v-1l.6 .6 .1-.5h.7l.2 .2v.5l-.2 .2M30.9 134.8v.8l.7 .1-.1-.3v-.5l.3-.2 .5 .1 .2 .3-.2 .6M30.9 131.9v-1l.6 .5v-.4l.3-.1h.5l.2 .3v.4l-.2 .3M30.9 132.6a.87 .87 0 0 1 .9-.3 .87 .87 0 0 1 .7 .7 1.08 1.08 0 0 1-1.6 0zM30.9 129.5a.87 .87 0 0 1 .9-.3 .87 .87 0 0 1 .7 .6 .89 .89 0 0 1-.9 .5 .89 .89 0 0 1-.7-.6zM30.9 128a.87 .87 0 0 1 .9-.3 .87 .87 0 0 1 .7 .6l-.4 .3a.9 .9 0 0 1-1.2-.5zM31.4 125.8h1.1M31.4 123.6h1.1"/>
<path d="M32.3 134.1h.2M32.5 125.1h-.9a.37 .37 0 0 0-.2 .3 .37 .37 0 0 0 .1 .4M32.5 124.3l-1 .1-.1 .4 .2 .3M32.5 122.9l-1 .1-.1 .4 .1 .2M32.5 122.2l-1 .1-.1 .3 .2 .3M39.3 139.4v-1l.6 .5 .1-.4h.9v.6l-.1 .3M39.9 127.8h1.1M39.9 125.7h1.1M40 132.9l.3 .2v.5a.6 .6 0 0 1-1 0v-.4a.97 .97 0 0 1 1.6 .2v.2M40 131.4l.3 .2v.4l-.3 .3-.6-.2-.1-.5 .2-.2a1.05 1.05 0 0 1 1.4 .4v.3M40 130.1l.3-.3h.6v.8l-.7 .1-.3-.9h-.4l-.2 .3 .1 .5 .5 .1 .1-.3M40.8 136.1h.1"/>
<path d="M40.9 137.3h-1.6l.5 .2v.2M40.9 135.1l-1.6-.7v1.1M40.9 136.8v.9M41 127.1h-.9l-.2 .3 .1 .4M41 126.4h-.9l-.2 .3 .2 .4M41 124.9h-.9l-.2 .3 .2 .5M41 124.2h-.9l-.2 .3 .2 .4M51.4 138.4v.3l.2 .2a1.23 1.23 0 0 0 1.5 0l-.1-.6-.6-.1-.3 .4v.3l.3 .2M52 131.6h1.1M52 129.4h1.1M52.2 135.1a.6 .6 0 0 1 .2 .8h-.9l-.1-.5a1.06 1.06 0 0 1 1.7 .2v.3M52.2 133.9l.1-.3h.5l.2 .1 .1 .5-.3 .3h-.3l-.3-.2-.1-.6-.2-.1a.44 .44 0 0 0-.5 .5 .44 .44 0 0 0 .6 .3l.2-.2"/>
<path d="M53 139.8h.1M53.1 137.3l-1.7-.7v1.1M53.1 130.9h-.9l-.2 .2 .2 .5M53.1 130.2h-.9l-.2 .2 .2 .5M53.1 128.7h-.9l-.2 .3 .2 .4M53.1 128.1h-.9l-.2 .1 .2 .5M61.2 138h1.1M62.3 139.6l-1 .1-.1 .3 .1 .3M62.3 138.8l-1 .1-.1 .4 .2 .3M62.3 137.4h-.9a.37 .37 0 0 0-.2 .3 .37 .37 0 0 0 .1 .3M62.3 136.7h-1l-.1 .4 .2 .3M97.3 126.6l.8-.1 .2-.2-.1-.4-.3-.1h-.6v1.6"/>
<path d="M97.7 126.6l.6 .8M99.3 125.7l-.5 1.2h1.1M99.6 126.3v1.1M109.8 124.6l.6-.1 .2-.3-.1-.2-.2-.2h-.5v1.6h.6l.2-.1 .1-.4-.4-.3M111.2 123.8h1.1l-1.1 1.6h1.1M112.9 124.2l.4-.4v1.6M112.9 125.4h.9M126.5 133.7a.54 .54 0 0 1 1 0 1.12 1.12 0 0 1-.4 1.5l-.4-.1a1.28 1.28 0 0 1-.2-1.4zM126.8 134.7l.8 .6M128.1 133.6l.3-.1h.4l.2 .1 .1 .4-.1 .2-.9 1h1M129.4 138.6h1.7l-1.7 1h1.7M129.6 136.9a.66 .66 0 0 0 0 .9 .66 .66 0 0 0 .7 .2l.6-.2a.52 .52 0 0 0 0-.9"/>
<path d="M132.5 139.7v.7l.8 .1v-.8h.8l.1 .2v.4l-.1 .2M132.5 138l1.7 .6-1.7 .5M136.7 138.9v.8h1.7v-.8M136.8 137.4l-.1 .6 .3 .3 .5-.2 .1-.6h.7v.8M137.5 139.1v.6M140.8 139.4v-.9l.7 .5 .2-.5h.7l.1 .2v.5l-.1 .2M140.8 136.9l1.7 .6-1.7 .5M145.1 139.7v.7l.7 .1-.1-.2 .1-.6 .2-.1 .5 .1 .2 .2v.4l-.2 .2M145.1 138l1.6 .6-1.6 .5M149.2 138.9h1.6l-1.6 .9h1.6M149.3 137.5l.3-.2a.85 .85 0 0 1 .9 0 .85 .85 0 0 1 .3 .8h-1.6zM153.4 138.9h1.6l-1.6 .9h1.6"/>
<path d="M153.5 137.5l.2-.2a.85 .85 0 0 1 .9 0 .85 .85 0 0 1 .4 .8h-1.6zM157.5 137.8h1.6l-1.6 .9h1.6M157.5 139.5h1.6M165.8 138.6l.4-.3a.9 .9 0 0 1 1.2 .4 .87 .87 0 0 1-.8 .5 .87 .87 0 0 1-.8-.6zM166.8 135.3l.3-.2 .7 .2a1.05 1.05 0 0 1-.4 1.4l-.5-.1a1.5 1.5 0 0 1-.1-1.3zM167 136.3l.3 .1 .6 .5M167 139.7v.8M167.4 139.6l-1.6 .6 1.6 .5M168.4 135.5l.5-.4v1.6M168.4 136.7h1M171.2 139.7v.8M171.6 139.6l-1.6 .6 1.6 .5"/>
<path d="M171.6 138.6h-1.6l.5 .5M171.6 138.2v.9M175.3 139.7v.8M175.7 139.6l-1.6 .6 1.6 .5M175.7 138.2v1l-.9-.9a.45 .45 0 0 0-.7 .2v.4l.2 .2M178.3 139.2v-1l.6 .5 .1-.4h.8l.2 .2v.5l-.2 .2M179.5 139.7v.8M180 139.6l-1.7 .6 1.7 .5M183 138.4h1.1M183.5 138.1v1l-1.2-.4M183.6 139.7v.8M184.1 139.6l-1.7 .6 1.7 .5"/>
<path d="M186.6 138.3v.8h.8l-.2-.2v-.4l.3-.3 .6 .1 .2 .2v.4l-.2 .2M187.7 139.7v.8M188.3 139.6l-1.7 .6 1.7 .5M189 133.3l.8-.1 .1-.2v-.5h-.9v1.6M189.4 133.3l.5 .8M190.5 132.9l.6-.4v1.6M190.5 134.1h1M203.9 128.1h1.9M203.9 127.1h1.9M203.9 124.8h1.9M203.9 123.7h1.9M204.5 131.4l.1 .4 .3 .2"/>
<path d="M204.5 133.6h1.3M204.5 132h1.3M204.5 128.7v.7M204.6 136.4l.3-.2h.5l.3 .2 .1 .4-.4 .3h-.5l-.4-.3zM204.6 134.7l.3-.2h.5l.3 .2 .1 .4-.4 .3h-.5l-.4-.3zM204.8 123.7v1.1M204.9 130l.2 .9h.3h.3v-.9M204.9 120.5l.1 .6a.45 .45 0 0 0 .7 .2v-.8M205.7 122.2v.7h-1.1a.6 .6 0 0 1 .2-.9h.1l.2 1M205.8 138h-1.9l1.4 .6-1.4 .5h1.9M205.8 132.9l-1.2 .1-.1 .4 .2 .2M205.8 130l-1.2 .1v.8"/>
<path d="M205.8 128.7l-.1 .4-.2 .1h-1.6M205.8 120.5l-1.2 .1v.7M206.5 137.1h1.5M207.1 138.2v.4h.2M207.1 135.4l.9 .3-.7 .3 .7 .3-.9 .2M207.1 133.1v.4l.2 .1M207.1 138.6h.9M207.1 133.6h.9M207.1 137.1v.4l.2 .3 .6-.1v-.6M207.4 139.3l.2 .7 .4-.2-.1-.5M207.4 134.2l.2 .7h.3l.1-.2-.1-.5M207.9 132.1l.1 .4-.2 .2h-.6l-.1-.2v-.4l.3-.1 .2 .7"/>
<path d="M208 139.3h-.8l-.1 .2v.4M208 134.2h-.8l-.1 .3v.4M209.3 139.9l.4-.2h.4l.3 .2v.3l-.3 .2h-.4l-.4-.2zM209.3 139.1h1.1M210.4 138.4h-.8a.37 .37 0 0 0-.3 .3 .37 .37 0 0 0 .2 .4M210.4 135.8v1l-1.1-1-.3 .1-.1 .2 .1 .6M211.7 138.4l.1 .3 .2 .1M211.7 138.8h1M211.8 137.4l.2-.2h.4l.2 .2 .1 .3-.1 .3h-.7l-.2-.3zM211.8 136l-.1 .4 .3 .3 .6-.1 .1-.2-.1-.4M212 134.7l.1 .6 .3 .1 .3-.1-.1-.6M212.7 134.7l-.9 .1v.5"/>
<path d="M212.7 133.8l-.2 .3h-1.3M215.6 137.5l-.1-.7-.2-.2-.5 .1v.8h1.6M216.4 135.7l-1.6-.7v1M216.4 136.6l-.8 .5M227 136.6h1.4l.2 .2v.6l-.2 .1h-1.4M228.6 135.4h-1.6l.5 .5M228.6 135v.9M15.4 158.1h57.1M15.4 156.3l1 1.8M17.3 156.3l-.9 1.8M20.6 156.3l.9 1.8M22.6 156.3l-1.1 1.8"/>
<path d="M25 155.8l1 1.9M26.9 155.8l-.9 1.9M32.4 156.5l1 1.9M34.3 156.5l-.9 1.9M41.1 157.8l75.9 .1M41.1 155.9l.9 1.9M43.1 155.9l-1.1 1.9M51.4 140.8a.68 .68 0 0 0 .8 .7h.6l.2-.1 .1-.6-.1-.1h-.8l-.1 .5 .3 .3M53 155.8l1 1.9M53.1 142.1v1l-.9-.9-.3-.1-.3 .1-.2 .3 .2 .5M54.9 155.8l-.9 1.9M60.6 151.2h11.9"/>
<path d="M60.6 157.7h11.9M60.6 153l.9-1.8 .9 1.8M60.6 155.8l.9 1.9M60.7 147.1a1.1 1.1 0 0 1 1.6 .2 .97 .97 0 0 1-1.6 .1zM60.7 145.5a1.35 1.35 0 0 1 1.6 .2 .89 .89 0 0 1-.8 .6 .89 .89 0 0 1-.8-.5zM60.7 144a1.1 1.1 0 0 1 1.6 .1l-.2 .5-.8 .1-.6-.2zM60.7 142.5a1.03 1.03 0 0 1 1.6 .2 1.1 1.1 0 0 1-1.6 .2zM61.2 149.4h1.1M61.2 140.3h1.1M61.5 151.5v6.2M61.7 149.1v1.1l-1.1-.5M62.1 148.5h.2"/>
<path d="M62.4 155.8l-.9 1.9M72 143.7h1M72 142.9v1.7M73 142.9v1.7M73.3 152v14.2M73.7 143l.6-.1 .2 .1 .1 .4-.1 .2-.9 1h1M97.5 157.6l-72.5 .1M137.5 141.4v-.9l-.6-.1-.2 .3v.7h1.7M138.4 140.4l-.9 .5M140.8 141.8v-1l.7 .6v-.3l.3-.3h.6l.1 .3v.4l-.1 .3M142.4 140.1h.1M149.3 140.6a.78 .78 0 0 0 .6 1 .78 .78 0 0 0 .9-.8l-.1-.3h-.5v.3"/>
<path d="M153.5 140.6a.78 .78 0 0 0 .6 1 .78 .78 0 0 0 .9-.8l-.2-.3h-.5v.3M157.5 140.1l1.6 .5-1.6 .6M168.9 157.8l-136.5 .6M193.2 143.7h.9M193.2 142.9v1.7M194.1 142.9v1.7M194.4 152v40.4M194.7 142.9h1l-.5 .7 .5 .2-.1 .6-.2 .2h-.5l-.2-.2M206.5 152.7v.7h1.5v-.7M206.5 149.8h1.5l-1.5 .8h1.5M206.5 141.4h1.5M206.5 140.7h1.5"/>
<path d="M206.7 154a.68 .68 0 0 0 .4 .9 .68 .68 0 0 0 .9-.6l-.1-.3M206.8 147.1h1l.2 .3a.46 .46 0 0 1-.4 .6l-1-.1a.52 .52 0 0 1 .2-.8zM207.1 146.4h1.4M207.1 143.9h.9M207.1 146.4v-.4l.2-.2h.6v.6M207.2 140.7v.7M207.2 152.9v.5M207.3 152.1l-.1-.8h-.6l-.1 .8h1.5M207.9 144.6l.1 .4-.2 .2h-.6l-.1-.2v-.4l.3-.1 .2 .7M208 143.3h-.9v.6M208 151.3l-.7 .4M208.9 153.6h.1"/>
<path d="M208.9 144.8l1.5 .5-1.5 .5M208.9 141h.1M209.3 142.7v.2l.4 .2M209.3 153.6h1.1M209.3 150.5h1.1M209.3 143.1h1.1M209.3 141h1.1M209.4 152.4l-.1 .4 .4 .2h.4l.3-.2-.1-.4M209.4 148.6l-.1 .5 .3 .1 .2-.1 .1-.5h.4v.6M209.4 141.8l-.1 .3 .3 .2 .2-.2 .1-.3h.4v.5M210.3 151.2l.1 .4-.3 .2-.7-.1v-.5l.4-.1v.7M210.3 147.4l.1 .5-.3 .1h-.7l-.1-.5 .5-.1v.6"/>
<path d="M210.3 143.8l.1 .4-.3 .3-.7-.1v-.6l.4-.1v.8M210.4 154.1v.7h-1.5M210.4 149.8h-.8a.37 .37 0 0 0-.3 .3 .37 .37 0 0 0 .2 .4M211.2 140.8h.2M211.3 154.1l-.1 .5 .3 .3a.57 .57 0 0 0 .5-.7l.3-.1 .3 .1v.7M211.7 152.2l.3 .4M211.7 148.5h1.2l.2 .1v.5M211.7 146.4l1 .4 .4 .3M211.7 153.1v.5M211.7 152.6h1M211.7 150.4h1M211.7 140.8h1"/>
<path d="M211.7 140.2h1.4M211.8 151.2l.2-.2h.4l.2 .2 .1 .3-.3 .3h-.4l-.3-.3zM211.8 148.5l-.1 .4 .3 .2h.6v-.6M211.8 141.4a.52 .52 0 0 0 .2 .8h.4l.2-.2v-.6M211.8 140.2l-.1-.5 .2-.2h.7l.1 .2-.1 .5M212 144.8v-.7h-.7l-.1 .7h1.5M212.6 142.8l.1 .4-.2 .2-.7-.1v-.5l.2-.1 .2 .7M212.7 153.1l-.2 .4h-1.3M212.7 149.8h-.9l-.1 .4 .2 .2M212.7 147.5l-.2 .3h-1.3M212.7 146.8l-1 .3M212.7 144l-.7 .5"/>
<path d="M219.3 142.9v1.7M219.3 143.7h1M220.3 142.9v1.7M220.6 152v49M221.4 151.2h36.6M221.4 157.7h27.3M221.7 142.9a.68 .68 0 0 0-.8 .7v.6l.2 .3 .5 .1 .2-.2 .1-.6-.3-.2h-.3l-.4 .2M234.4 154.4h.9M234.8 154.4v1.6M235.8 155.2h.7l.3-.3v-.3l-.3-.2h-.7v1.6M237.4 154.6l.2-.2h.4l.4 .2v.2l-.1 .3-.9 .9h1M246.8 155.8l1 1.9"/>
<path d="M247.8 151.2v6.5M247.8 151.2l.9 1.8M247.8 151.2l-1 1.8M248.7 155.8l-.9 1.9M250.3 158.3h1.1M250.3 156.1h1.1M251.4 157.5l-1 .1-.1 .4 .2 .3M251.4 156.8h-.8a.35 .35 0 0 0-.3 .4 .35 .35 0 0 0 .3 .3M251.4 155.3l-1 .1-.1 .4 .2 .3M251.4 154.6l-1 .1-.1 .5 .3 .1M256.1 149.3l1 1.9M258 149.3l-.9 1.9"/>
<path d="M66.5 170.6l31.7 .1M66.5 170.6l1.9 1.1M66.8 165.2h6.5M66.8 165.2l1.8 1M67 176.7l1.8 1M68.4 169.7l-1.9 .9M68.6 164.3l-1.8 .9M68.8 175.7l-1.8 1M71.4 164.3l1.9 .9M73.3 165.2l-1.9 1M74.8 168.4l.5-.5v1.6M74.8 169.5h.9"/>
<path d="M76.2 164l-.4 1.1h1M76.7 164.6v1.1M77.3 168.6v.2l-.3 .2-.5-.1-.2-.3 .1-.6h.9v1.1a.63 .63 0 0 1-.8 .4M77.5 165.6v.1M78 169.4v.1M78.4 164.2l.2-.2a.95 .95 0 0 1 .5 .9 .95 .95 0 0 1-.5 .8l-.2-.1-.2-.5zM78.6 167.9h1l-.5 .6 .4 .1 .1 .3-.1 .5-.2 .1h-.4l-.3-.1M79.9 164.2l.2-.2 .5 .2v1.4l-.3 .1a.91 .91 0 0 1-.4-1.5zM81.2 167.9h-.9l-.1 .8 .3-.2 .6 .1 .1 .8-.3 .1h-.4l-.3-.1M81.5 164.1l.2-.1a.89 .89 0 0 1 .6 .9 .89 .89 0 0 1-.6 .8 1.35 1.35 0 0 1-.2-1.6zM82 168l.3-.1a.87 .87 0 0 1 .5 .9 .87 .87 0 0 1-.6 .7l-.4-.5zM83 164.2l.3-.2a.95 .95 0 0 1 .5 .9 .95 .95 0 0 1-.5 .8l-.3-.1-.2-.5z"/>
<path d="M83.4 168.2a.45 .45 0 0 1 .7-.2 1.19 1.19 0 0 1-.2 1.5h-.3l-.2-.3zM84.9 173.9h1l-.5 .6 .5 .1v.7l-.3 .2h-.5l-.2-.2M85.7 164.8l.3-.2 .4 .1v1M85.7 164.6v1.1M86.2 168.6l.3-.2 .4 .1 .1 1M86.2 168.4v1.1M86.4 164.9l.3-.3 .4 .1 .1 1M86.6 174.3l.4-.4v1.6M86.6 175.5h.9M87 168.7l.2-.3 .4 .1 .1 1M87.9 164.8l.1-.1a.36 .36 0 0 1 .6 .2v.8M87.9 164.6v1.1"/>
<path d="M88.2 175.3v.2M88.4 168.6l.3-.2 .3 .1 .1 1M88.4 168.4v1.1M88.6 164.9l.3-.3 .4 .1 .1 1M88.9 174l.2-.1h.4l.3 .1v.5l-.9 1h.9M89.1 168.7l.3-.3 .4 .1 .1 1M90.4 173.9h1.1l-.7 1.6M92.2 173.9h.5a1.16 1.16 0 0 1-.1 1.6 .91 .91 0 0 1-.4-1.6zM93.6 173.9l.6-.1 .2 .1 .1 .4-.1 .2-.9 1h1M96.3 169.7l1.9 1M96.5 174.5l.1-.1 .5 .1 .1 1M96.5 174.4v1.1"/>
<path d="M97.2 174.6a.35 .35 0 0 1 .3-.2 .35 .35 0 0 1 .3 .2v.9M98.2 170.7l-1.9 1M98.6 174.5l.2-.1 .5 .1 .1 1M98.6 174.4v1.1M99.4 174.6l.1-.2 .5 .1v1M116.3 175.6l1.9 .9-1.9 1M117.9 177.5v-70.8l.3 70.8M119.8 175.6l-1.9 1 1.9 .9M126.4 174.3l.5-.5v1.7M126.4 175.5h1M128.9 174.5a.54 .54 0 0 1-.9 0l.1-.6 .5-.1a1.06 1.06 0 0 1-.2 1.7h-.3M129.6 175.3v.2"/>
<path d="M131.1 173.8a.63 .63 0 0 0-.8 .4l.1 1.2h.7l.2-.3v-.4a.59 .59 0 0 0-1-.1v.1M131.9 174.3l.4-.5v1.7M131.9 175.5h.9M133.6 173.9l.2-.1 .4 .1v1.4l-.2 .2a.91 .91 0 0 1-.4-1.6zM135.2 173.9l.1-.1a.89 .89 0 0 1 .6 .8 .89 .89 0 0 1-.6 .9 1.35 1.35 0 0 1-.1-1.6zM137.9 174.5h.1a.36 .36 0 0 1 .6 .1v.9M137.9 174.4v1.1M138.6 174.6l.2-.2 .3 .1 .1 1M140.1 174.5l.2-.1 .4 .1 .1 1M140.1 174.4v1.1M140.8 174.6a.35 .35 0 0 1 .3-.2 .35 .35 0 0 1 .3 .2v.9M148.2 175.6l1.8 1"/>
<path d="M150 176.6l-83 .1M150 176.6l-1.8 .9M198.4 167.2l.6 1.6 .5-1.6M200.1 168.2h1.2M203 167.3a.68 .68 0 0 0-.9 .2v.9a.55 .55 0 0 0 .9 .2M203.8 167.2v1.2l.2 .4h.3l.4-.4v-1.2M205.2 167.2h.9M205.7 167.2v1.6M249.9 165.1a1.19 1.19 0 0 1 1.5 .1 .83 .83 0 0 1-.8 .6 .83 .83 0 0 1-.8-.6zM249.9 163.5a.87 .87 0 0 1 .9-.3 .87 .87 0 0 1 .6 .7 1.08 1.08 0 0 1-1.6 0zM249.9 162a.9 .9 0 0 1 1.5 .3 .91 .91 0 0 1-1.6-.1zM249.9 160.4l.2-.2h1a.48 .48 0 0 1 .3 .6 .48 .48 0 0 1-.6 .4 .76 .76 0 0 1-1-.5z"/>
<path d="M250.3 167.3h1.1M250.9 167.1v1l-1.2-.3M251.2 166.5h.2M66.8 184.6l1.8 .9M66.8 191.5h127.6M66.8 191.5l1.8 .9M66.8 199.9h153.8M66.8 199.9l1.8 1.1M68.6 183.6l-1.8 1M68.6 190.5l-1.8 1M68.6 199l-1.8 .9M111.4 181.8a.7 .7 0 0 0-.9 .7v.6l.2 .2 .5 .1 .3-.3v-.3l-.3-.4-.5 .1-.2 .3"/>
<path d="M112.1 182l.1-.1a.6 .6 0 0 1 .9 .2l-.1 .4-.9 .9h1M113.7 183.3v.1M114.4 181.8h1l-.6 1.6M116.9 181.8h-.8l-.1 .8 .3-.2 .5 .1 .2 .3-.1 .5-.3 .1-.6-.1M117.7 181.9h.6a1.19 1.19 0 0 1-.1 1.5 .91 .91 0 0 1-.5-1.5zM119.3 181.9l.4-.1a.87 .87 0 0 1 .4 .9 .87 .87 0 0 1-.6 .7l-.2-.1-.1-.5zM122 182.5l.1-.1a.36 .36 0 0 1 .6 .2v.8M122 182.3v1.1M122.7 182.6l.3-.3 .3 .1 .1 1M122.9 188.7h1.1l-.7 1.7M124.2 182.5l.2-.2 .4 .1 .1 1M124.2 182.3v1.1"/>
<path d="M124.8 189.4l-.2-.3 .2-.4 .6 .1 .1 .3-.2 .3h-.5a.6 .6 0 0 0 0 1h.4l.3-.4v-.3l-.3-.3M124.9 182.6a.35 .35 0 0 1 .4-.3 .35 .35 0 0 1 .3 .3v.8M126.2 190.2v.2M127 188.8l.5-.1 .3 .3v1l-.3 .4a.91 .91 0 0 1-.5-1.6zM128.7 188.8l.1-.1a.89 .89 0 0 1 .6 .8 .89 .89 0 0 1-.6 .9l-.3-.7zM130.2 188.8l.4-.1a1.2 1.2 0 0 1 0 1.7 .91 .91 0 0 1-.4-1.6zM131.7 188.8l.3-.1a.89 .89 0 0 1 .6 .8 .89 .89 0 0 1-.6 .9l-.3-.2-.1-.5zM134.5 189.4l.4-.1 .3 .1v1M134.5 189.3v1.1M135.2 189.4l.2-.1 .4 .1v1M136.6 189.4l.5-.1 .3 .1v1M136.6 189.3v1.1"/>
<path d="M137 197.9l-.1 .3h-.5l-.3-.3v-.4a.54 .54 0 0 1 .9 0 1.29 1.29 0 0 1-.4 1.3h-.3M137.4 189.4l.2-.1 .4 .1v1M138 197.1l-.4 1.2h1M138.5 197.7v1.1M139.3 198.7v.1M140.1 197.5l.3-.3a.87 .87 0 0 1 .6 .8 .87 .87 0 0 1-.6 .8l-.2-.1-.2-.5zM141.6 197.5a.47 .47 0 0 1 .4-.3 .47 .47 0 0 1 .5 .3v1a.48 .48 0 0 1-.6 .3 .48 .48 0 0 1-.4-.6zM143.5 197.2a.83 .83 0 0 1 .6 .8 .83 .83 0 0 1-.6 .8l-.3-.3a1.08 1.08 0 0 1 .3-1.3zM144.7 197.5a.45 .45 0 0 1 .7-.2 1.19 1.19 0 0 1-.2 1.5h-.3l-.2-.3zM147.5 197.9l.3-.2 .4 .1 .1 1M147.5 197.7v1.1M148.3 198l.2-.3 .4 .1 .1 1"/>
<path d="M149.7 197.9l.3-.2 .3 .1 .1 1M149.7 197.7v1.1M150.4 198l.3-.3 .4 .1 .1 1M167.6 183.6l1.9 .9M169.5 184.5l-102.7 .1M169.5 184.5l-1.9 1M192.6 190.5l1.8 1M194.4 191.5l-1.8 .9M218.7 199l1.9 .9M220.6 199.9l-1.9 1.1"/>
</g>
<g fill="#000">
<path d="M227.6 53.4l.2-.1h2.4a1.75 1.75 0 0 1 1.7 1.7 1.75 1.75 0 0 1-1.5 1.8h-1.3v.8h.5v.7h-.7v.3l1.3-.1 .1 .4-.3 .4v1h.8v-1.1l-.3-.4h.2v.2l.4-.2-.1-.1-.5 .1v-.2l.4-.2 1.3 .3v-.2l-.3 .1 .3-.4 .5 .6 .1 .7v-.2l.5-.3-.3 .9 1.4 2.2v-2.8l-1-.1-.1-.4 .6 .2-.1-.3-.5 .1 .1-.5h.4l.3 .3h1.4v3.4h2.1l-.1-.3a1.63 1.63 0 0 0-.9-1.3l-.4-.6h.3l.5 .7-.5-.7h-.3h.6l-.1-.4-.2-.1h.8l1 2.8h.1l.8-2.2h-1.4l-.1-.5h.2v.3l.3 .1h1l.2-.5-.6-.1v-.4h1.5l.2 .2 .2-.2h-1.9v-.2h1.4l-.7-.7-.7 .3-.8 .1 .2 .6-.3 .3v.2h-.2v-.2l-1.2 .1-.4-.1v-.4h1.5l.2 .2 .2-.3-.4 .1h-1.5v-.2h1.3l.3-.3h-2l-.3-.5 .6 .2-.1-.3-.5 .1 .2-.3 3.1 .1a.92 .92 0 0 0 .6-1.6h-.4h1.1l.1-.2-.1 .2-2.7-.2h3h-3l-.1 1.8h-.6a1.06 1.06 0 0 0-1.2-1.2 1.99 1.99 0 0 1-2 1.9l-.1-.1-.7-.4-.5-.6v-.3l.6 .1a1.06 1.06 0 0 0 1.1 .6 1.06 1.06 0 0 0 .9-.7h-2.6v-1.6l.7-.1-.7 .1v-.2h.8l.2-.4-.2 .4h-.8l-.1-1.2-.5-.1v-.5h1.8v.5l-.6 .2v.8l.4-.4a.68 .68 0 0 1-.4 1.1v1.2h2.1v-.5h.6a1.13 1.13 0 0 1 1.1 .4h.1l-.5-.5-1.3 .1v-2.3h-.5l-.2-.1v-.5h1.7v.5l-.4 .1v2.1h.6l.6 .4v-.6h3.8l.1-.2-.1 .2h-3.8v-.4l2.9 .1-2.9-.1v-.2h3h-3v-1.3h.6l.1 1.3h.7l.9-.3 .1-.4h.7l.4-.7-.1-.1-.3 .8h-.7l-.1-.3-.4-.2-2.4-.2v-.5h2.3l1 .5 .3-.2 .8-.2-.2 1.5-.7 .6 .9 .1h-.7l.7-.3h.3l-.3 .6a1.13 1.13 0 0 0-.4 1.1l-.3 .7 1.1 1.1-.2 .4v4h-2l-.4 .4-.2-.2-.2-.4 2.6 .1v-3.8h-.5l-.1 .1-1.1 3.6h-.9l-.1-.2h-2.9v.7h-.3l-.2-.2-.4-.6h3.8l-.2-.6h-2.3v-2.9h-.2l-.2 .5v3h-.9l-.9-1.4h-.4v1.5l.1 .2v.5h-1.7l.1-1.1h-1.5l.2 1h-1.7v-.6h.6l-.1-.3h.7v.2l.1 .1 .1-.5h1.7l.1 .6h1.1l.1-1.7 .4-.2-.8-1.1v3h-.7l.1-.2v-.6h-2.2v.4h-.7v-.5h2.9v-1.3l-2.2-.1h2.2v-.9h1.3l.2-.5-.2 .5h-1.3v-.4l-.5-.1-.1 1.2h-1l-.1-1.1-.3-.1v1.4h-.2v-1.4v2.8h-.7v-.9l-.4-.4 .1-.1 .3 .4-.4-.4v-.1h.4v-1.3h-.9l-.2-.4 .2 .2 .4-.2h1.6l.2 .2 .1-.1v-.2l-.2-.1-.1 .2h-1.6l-.3-.2-.1 .2h-.2l.3-.4 .9 .2v-.4l-.7 .1a.34 .34 0 0 1-.4-.5l.5 .2 .1-.2-.3-.1-.3 .1 .1-.2h.7v-1l-.2-.3a1.19 1.19 0 0 1-.9-1.5l.8 .5 .1 .8-.8-1 .2 .4 .7 .8v-.8h.7l.3-.4-.3 .4h-.7v-1.6h.7v.8l.3-.2 .2 .1v.8l-.2 .8a1.48 1.48 0 0 0 1.8-1.2l-.2-.6a.63 .63 0 0 0-.8-.4l-2.4-.1-.2-.3 .5 .2 .1-.3-.4-.1-.2 .2zM82.5 130.2l.6-.1 2.2 .2a1.72 1.72 0 0 1 1.2 2 1.72 1.72 0 0 1-1.8 1.4l-.9 .1v.7h.5v.6h-.7v.4l1.3-.1 .2 .3-.3 .4v1.1h.8v-.8l-.3-.7 .2 .2 .4-.2-.2-.1-.4 .1 .1-.3 1.6 .2v-.2l-.3 .1 .3-.4 .5 .7v.6l.2-.4 .3-.1-.3 .9 1.4 2.1v-2.8h-.7l-.3-.2h.5v-.3l-.5 .2v-.6h.4v.2l.3 .1h1.4v3.4h2.1l-.3-.7a1.04 1.04 0 0 0-.8-1l-.3-.5h.3l.6 .7-.5-.7h-.4v-.1l.6 .1-.2-.6h.7l1.1 3 .8-2.4h-1.4v-.4h.1l.1 .4h1.2l.2-.6h-.5v-.4h1.4l.4 .2v-.3l-1.8 .1v-.2h1.3l-.7-.7-.6 .2-.9 .1 .2 .9-.3 .1v.2h-.1l-.2-.2h-1h-.4v-.4h1.4l.2 .2 .2-.3-1.8 .1v-.2h1.4l.1-.4h-2l-.3-.3h.2l.1 .2 .4-.2-.2-.3-.3 .1v.2h-.2l.2-.4 3.3 .1 .5-.4 .1-.6-.2-.6-.4-.1h1.3h-1.3l-1.6-.1h3h-3l-.1 1.8h-.5v-.6l-.7-.6h-.5l-.1 .4a1.76 1.76 0 0 1-1.6 1.5 1.8 1.8 0 0 1-1.7-1.4l.7 .1a1.06 1.06 0 0 0 1 .6 1.06 1.06 0 0 0 .9-.7h-2.6v-1.6l.8-.1-.8 .1v-.2h.8l.2-.4-.2 .4h-.8l-.1-1.2-.5-.1v-.5h1.8v.5l-.6 .2v.8l.5-.3a.81 .81 0 0 1-.5 1v1.2h2.1v-.5h.7a1.19 1.19 0 0 1 1.2 .5l-.2-.3a.88 .88 0 0 0-1.1-.2h-.6v-2.2l-.6-.1-.1-.6h1.8v.6h-.5v2.1h.7l.6 .4v-.6l3.8-.1-3.8 .1v-.5h2.8h-2.8v-.1h2.9h-2.9l-.1-1.3h.6l.1 1.3h1a.68 .68 0 0 0 .8-.7h.7l.3-.8-.4 .8h-.6a.74 .74 0 0 0-.8-.5l-2.2-.1v-.6l2.6 .1 .8 .4 .1-.1 .9-.3-.2 1.5-.6 .7 .8 .1-.7-.1 1-.3-.3 .6-.3 .3-.2 1.1-.2 .4 1.1 1-.2 .5v4l-1.9-.1-.2 .4-.3 .1-.4-.6 2.6 .1v-3.9h-.4l-1.2 3.8h-1l-.1-.2h-2.8v.7h-.4l-.6-.8h3.8l-.1-.6-2.3-.1v-2.1l-.2-.7h-.2v3.5h-1l-.8-1.4h-.5v1.5l.1 .1v.6h-1.6v-1.1h-1.5v.4h.2v.7h-1.7v-.7h.6v-.3h.6v.2l.1 .1 .1-.5h1.8l.1 .6h1.1v-1.7h.3l.1-.2-.7-1v2.9h-.8l.2-.1v-.8h-2.3v.5h-.6v-.5h2.9v-1.3l-2.2-.1 2.2 .1v-1h1.2l.3-.5-.3 .5h-1.2v-.5h-.6l-.1 1.1h-1l-.1-1.1h-.3v1.4h-.1v-1.4l-.1 2.8h-.6l-.1-.9-.3-.2v-.3l.3 .3-.3-.3v-.2l.3 .1 .1-.2-.1-1.1h-.8l-.3-.2v-.2l.2 .2h.3l.1-.2h1.6l.2 .2 .1-.1v-.2h-.3v.1h-1.6l-.1-.1h-.3l-.2 .1 .2-.3 1 .1v-.4h-.9l-.2-.2 .1-.1 .3 .2 .2-.2-.2-.3-.4 .3 .1-.3 .1-.1 .6 .1v-1.2l-.4-.2a.89 .89 0 0 1-.6-1.4l.3 .2a1.4 1.4 0 0 1 .6 1.2l-.9-1.1 .2 .4 .7 .8 .1-.8h.7l.3-.4-.3 .4h-.7l-.1-1.6h.7v.8l.5-.2-.1 1.7h.8a1.12 1.12 0 0 0 .9-1.3 1.12 1.12 0 0 0-1.3-.9h-2l-.3-.4 .2 .1h.3l.1-.1-.1-.2-.5 .2z"/>
<circle cx="68.9" cy="57.8" r=".47"/>
<circle cx="70.2" cy="54.8" r=".47"/>
<circle cx="73.2" cy="57.8" r="2.92"/>
<circle cx="73.2" cy="53.6" r=".47"/>
<circle cx="76.3" cy="54.8" r=".47"/>
<circle cx="77.6" cy="57.8" r=".47"/>
<circle cx="190.1" cy="57.8" r=".47"/>
<circle cx="191.3" cy="54.8" r=".47"/>
<circle cx="194.3" cy="57.8" r="2.92"/>
<circle cx="194.3" cy="53.6" r=".47"/>
<circle cx="197.4" cy="54.8" r=".47"/>
<circle cx="198.6" cy="57.8" r=".47"/>
<circle cx="216.2" cy="57.8" r=".47"/>
<circle cx="217.5" cy="54.8" r=".47"/>
<circle cx="220.6" cy="57.8" r="2.92"/>
<circle cx="220.6" cy="53.6" r=".47"/>
<circle cx="223.6" cy="54.8" r=".47"/>
<circle cx="224.8" cy="57.8" r=".47"/>
<circle cx="70.2" cy="60.9" r=".47"/>
<circle cx="73.2" cy="62.1" r=".47"/>
<circle cx="76.3" cy="60.9" r=".47"/>
<circle cx="98.8" cy="75.9" r=".38"/>
<circle cx="114.3" cy="64.5" r=".89"/>
<circle cx="118.4" cy="64.5" r=".89"/>
<circle cx="119.9" cy="68.5" r=".38"/>
<circle cx="122.6" cy="64.5" r=".89"/>
<circle cx="126.7" cy="64.5" r=".89"/>
<circle cx="126.9" cy="68.3" r=".38"/>
<circle cx="130.9" cy="64.5" r=".89"/>
<circle cx="135" cy="64.5" r=".89"/>
<circle cx="139.3" cy="64.5" r=".89"/>
<circle cx="143.4" cy="64.5" r=".89"/>
<circle cx="144.9" cy="68.7" r=".38"/>
<circle cx="147.6" cy="64.5" r=".89"/>
<circle cx="149.5" cy="72.1" r=".38"/>
<circle cx="151.7" cy="64.5" r=".89"/>
<circle cx="158.3" cy="71.8" r=".38"/>
<circle cx="158.3" cy="64.5" r=".89"/>
<circle cx="162.5" cy="71.8" r=".38"/>
<circle cx="162.5" cy="64.5" r=".89"/>
<circle cx="166.5" cy="71.8" r=".38"/>
<circle cx="166.7" cy="64.5" r=".89"/>
<circle cx="170.9" cy="64.5" r=".89"/>
<circle cx="175" cy="79.4" r=".38"/>
<circle cx="175" cy="64.5" r=".89"/>
<circle cx="179.2" cy="64.5" r=".89"/>
<circle cx="183.3" cy="64.5" r=".89"/>
<circle cx="187.5" cy="64.5" r=".89"/>
<circle cx="189.1" cy="76.5" r=".38"/>
<circle cx="191.3" cy="60.9" r=".47"/>
<circle cx="192.7" cy="76.3" r=".97"/>
<circle cx="192.7" cy="72.1" r=".97"/>
<circle cx="194.3" cy="62.1" r=".47"/>
<circle cx="197.4" cy="60.9" r=".47"/>
<circle cx="209.3" cy="79.4" r=".38"/>
<circle cx="211.6" cy="73" r=".97"/>
<circle cx="215.7" cy="73" r=".97"/>
<circle cx="217.5" cy="60.9" r=".47"/>
<circle cx="220" cy="73" r=".97"/>
<circle cx="220.6" cy="62.1" r=".47"/>
<circle cx="223.6" cy="60.9" r=".47"/>
<circle cx="224.1" cy="73" r=".97"/>
<circle cx="228.3" cy="76.6" r=".38"/>
<circle cx="228.3" cy="73" r=".97"/>
<circle cx="232.4" cy="73" r=".97"/>
<circle cx="69.6" cy="80.4" r="1.31"/>
<circle cx="76.8" cy="80.4" r="1.48"/>
<circle cx="93.6" cy="97.8" r=".38"/>
<circle cx="94.5" cy="92.2" r="1.06"/>
<circle cx="94.5" cy="81.5" r="1.06"/>
<circle cx="101.9" cy="92.2" r="1.06"/>
<circle cx="101.9" cy="81.5" r="1.06"/>
<circle cx="114.7" cy="80.9" r="2.07"/>
<circle cx="124.2" cy="80" r="1.23"/>
<circle cx="127.6" cy="80" r=".72"/>
<circle cx="131.7" cy="80" r=".72"/>
<circle cx="131.8" cy="86" r=".38"/>
<circle cx="135.9" cy="88.3" r=".38"/>
<circle cx="135.9" cy="80" r=".72"/>
<circle cx="138.1" cy="92.5" r=".38"/>
<circle cx="140" cy="88.3" r=".38"/>
<circle cx="140" cy="80" r=".72"/>
<circle cx="144.9" cy="90.9" r=".38"/>
<circle cx="147.2" cy="81.3" r=".38"/>
<circle cx="152.8" cy="80.9" r="2.07"/>
<circle cx="158.5" cy="81.7" r=".38"/>
<circle cx="160" cy="93.8" r=".38"/>
<circle cx="164.1" cy="89.7" r=".38"/>
<circle cx="164.1" cy="96.7" r="1.06"/>
<circle cx="169.4" cy="84.4" r="1.23"/>
<circle cx="174.8" cy="96.7" r="1.06"/>
<circle cx="176.9" cy="87.6" r=".38"/>
<circle cx="177" cy="92.9" r=".38"/>
<circle cx="180.6" cy="92.5" r=".38"/>
<circle cx="180.6" cy="87.6" r=".38"/>
<circle cx="180.6" cy="98.5" r=".38"/>
<circle cx="182.5" cy="95.8" r=".38"/>
<circle cx="184.5" cy="84.3" r=".38"/>
<circle cx="184.5" cy="92.5" r=".38"/>
<circle cx="189.4" cy="80.5" r=".38"/>
<circle cx="189.4" cy="85" r=".38"/>
<circle cx="192.4" cy="98.1" r=".38"/>
<circle cx="192.7" cy="84.7" r=".97"/>
<circle cx="192.7" cy="80.5" r=".97"/>
<circle cx="192.7" cy="93" r=".97"/>
<circle cx="192.7" cy="88.8" r=".97"/>
<circle cx="211.4" cy="90.9" r=".38"/>
<circle cx="212.4" cy="85.8" r=".38"/>
<circle cx="215.7" cy="91.7" r=".89"/>
<circle cx="215.7" cy="87.5" r=".89"/>
<circle cx="217.6" cy="83.7" r=".38"/>
<circle cx="220" cy="91.7" r=".89"/>
<circle cx="220" cy="87.5" r=".89"/>
<circle cx="221.8" cy="99.1" r=".38"/>
<circle cx="222.3" cy="83.2" r=".38"/>
<circle cx="224.1" cy="91.7" r=".89"/>
<circle cx="224.1" cy="87.5" r=".89"/>
<circle cx="224.3" cy="84.2" r=".38"/>
<circle cx="228" cy="96.1" r=".38"/>
<circle cx="228.3" cy="91.7" r=".89"/>
<circle cx="228.3" cy="87.5" r=".89"/>
<circle cx="232.2" cy="97.2" r=".38"/>
<circle cx="232.4" cy="91.7" r=".89"/>
<circle cx="232.4" cy="87.5" r=".89"/>
<circle cx="235.3" cy="88.8" r=".38"/>
<circle cx="235.3" cy="94.1" r=".38"/>
<circle cx="94.5" cy="104.3" r=".38"/>
<circle cx="94.5" cy="119.2" r="1.06"/>
<circle cx="94.5" cy="108.5" r="1.06"/>
<circle cx="101.9" cy="119.2" r="1.06"/>
<circle cx="101.9" cy="108.5" r="1.06"/>
<circle cx="102.4" cy="103" r=".38"/>
<circle cx="106.3" cy="103" r=".38"/>
<circle cx="107.6" cy="119.4" r=".38"/>
<circle cx="114.7" cy="119.9" r="2.07"/>
<circle cx="149.5" cy="106.3" r=".38"/>
<circle cx="152.8" cy="119.9" r="2.07"/>
<circle cx="157.7" cy="100.8" r=".38"/>
<circle cx="159.3" cy="116.1" r=".38"/>
<circle cx="164.1" cy="104.1" r="1.06"/>
<circle cx="174" cy="112" r="2.92"/>
<circle cx="174.8" cy="104.1" r="1.06"/>
<circle cx="180.6" cy="103" r=".38"/>
<circle cx="186.7" cy="114.6" r=".38"/>
<circle cx="187.1" cy="118.7" r=".38"/>
<circle cx="187.8" cy="110.2" r=".38"/>
<circle cx="189.4" cy="101" r=".38"/>
<circle cx="190.2" cy="110.4" r=".89"/>
<circle cx="190.2" cy="114.6" r=".89"/>
<circle cx="190.2" cy="106.3" r=".89"/>
<circle cx="190.2" cy="118.8" r=".89"/>
<circle cx="194.3" cy="114.6" r=".89"/>
<circle cx="194.3" cy="110.4" r=".89"/>
<circle cx="194.3" cy="106.3" r=".89"/>
<circle cx="194.3" cy="118.8" r=".89"/>
<circle cx="194.6" cy="101.2" r=".38"/>
<circle cx="218.9" cy="101.3" r=".38"/>
<circle cx="226.1" cy="109.6" r=".38"/>
<circle cx="234.4" cy="113.6" r=".97"/>
<circle cx="234.4" cy="109.5" r=".97"/>
<circle cx="242" cy="113.7" r=".38"/>
<circle cx="93.9" cy="124.3" r=".38"/>
<circle cx="107.6" cy="132.8" r=".38"/>
<circle cx="107.6" cy="136.4" r=".89"/>
<circle cx="120.1" cy="128.9" r=".38"/>
<circle cx="120.1" cy="136.4" r=".89"/>
<circle cx="160" cy="132.3" r=".38"/>
<circle cx="160" cy="137.2" r=".38"/>
<circle cx="160.6" cy="128.9" r=".38"/>
<circle cx="161.6" cy="138" r=".38"/>
<circle cx="161.6" cy="131.1" r=".38"/>
<circle cx="169.8" cy="139.3" r=".97"/>
<circle cx="174" cy="139.3" r=".97"/>
<circle cx="178.1" cy="139.3" r=".97"/>
<circle cx="189.4" cy="125.7" r=".38"/>
<circle cx="190.2" cy="122.9" r=".89"/>
<circle cx="191.9" cy="127.8" r=".38"/>
<circle cx="192.2" cy="121.3" r=".38"/>
<circle cx="194.3" cy="122.9" r=".89"/>
<circle cx="195.2" cy="138.9" r=".38"/>
<circle cx="215.6" cy="124" r=".38"/>
<circle cx="219.5" cy="139.9" r=".38"/>
<circle cx="219.9" cy="133.2" r=".38"/>
<circle cx="220.4" cy="130.6" r=".38"/>
<circle cx="228.9" cy="138.1" r=".38"/>
<circle cx="68.9" cy="151.1" r=".47"/>
<circle cx="70.2" cy="148.1" r=".47"/>
<circle cx="70.2" cy="154.2" r=".47"/>
<circle cx="73.2" cy="151.1" r="2.92"/>
<circle cx="73.2" cy="146.8" r=".47"/>
<circle cx="73.2" cy="155.4" r=".47"/>
<circle cx="76.3" cy="148.1" r=".47"/>
<circle cx="76.3" cy="154.2" r=".47"/>
<circle cx="77.6" cy="151.1" r=".47"/>
<circle cx="107.6" cy="143.8" r=".38"/>
<circle cx="129.3" cy="143.5" r=".89"/>
<circle cx="133.4" cy="143.5" r=".89"/>
<circle cx="137.6" cy="143.5" r=".89"/>
<circle cx="141.7" cy="143.5" r=".89"/>
<circle cx="143.6" cy="147.1" r=".38"/>
<circle cx="145.9" cy="143.5" r=".89"/>
<circle cx="147.7" cy="147.1" r=".38"/>
<circle cx="150" cy="143.5" r=".89"/>
<circle cx="154.2" cy="143.5" r=".89"/>
<circle cx="158.3" cy="143.5" r=".89"/>
<circle cx="164.1" cy="140.9" r=".38"/>
<circle cx="166.7" cy="143.5" r=".89"/>
<circle cx="168.6" cy="142.2" r=".38"/>
<circle cx="170.9" cy="143.5" r=".89"/>
<circle cx="175" cy="143.5" r=".89"/>
<circle cx="179.2" cy="143.5" r=".89"/>
<circle cx="181.5" cy="141.6" r=".38"/>
<circle cx="183.3" cy="143.5" r=".89"/>
<circle cx="185.6" cy="145" r=".38"/>
<circle cx="187.5" cy="143.5" r=".89"/>
<circle cx="190.1" cy="151.1" r=".47"/>
<circle cx="191.3" cy="148.1" r=".47"/>
<circle cx="191.3" cy="154.2" r=".47"/>
<circle cx="194.3" cy="151.1" r="2.92"/>
<circle cx="194.3" cy="146.8" r=".47"/>
<circle cx="194.3" cy="155.4" r=".47"/>
<circle cx="197.4" cy="154.2" r=".47"/>
<circle cx="197.4" cy="148.1" r=".47"/>
<circle cx="198.6" cy="151.1" r=".47"/>
<circle cx="216.2" cy="151.1" r=".47"/>
<circle cx="217.5" cy="148.1" r=".47"/>
<circle cx="217.5" cy="154.2" r=".47"/>
<circle cx="220.6" cy="151.1" r="2.92"/>
<circle cx="220.6" cy="155.4" r=".47"/>
<circle cx="220.6" cy="146.8" r=".47"/>
<circle cx="223.6" cy="148.1" r=".47"/>
<circle cx="223.6" cy="154.2" r=".47"/>
<circle cx="224.8" cy="151.1" r=".47"/>
<circle cx="225.6" cy="142" r=".38"/>
<circle cx="235.3" cy="151.1" r="1.23"/>
</g>
<path d="M202.2 51.5v106" fill="none" stroke="#000" stroke-width=".42"/>
</svg>
